VERSION 5.7 ;
  NOWIREEXTENSIONATPIN ON ;
  DIVIDERCHAR "/" ;
  BUSBITCHARS "[]" ;
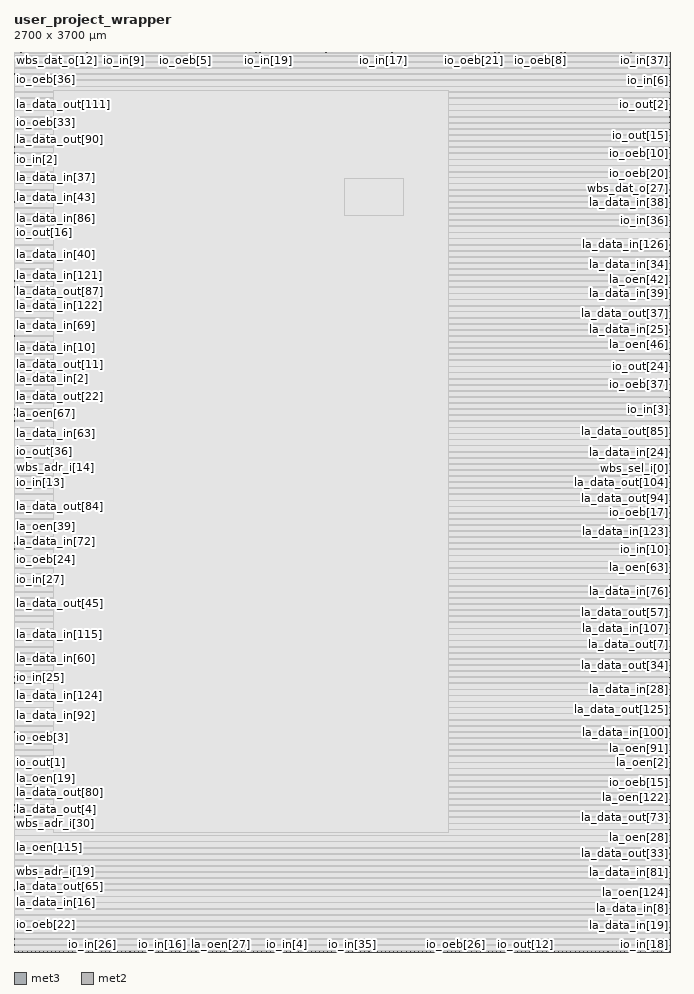
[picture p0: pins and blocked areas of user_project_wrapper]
MACRO user_project_wrapper
  CLASS BLOCK ;
  FOREIGN user_project_wrapper ;
  ORIGIN 0.000 0.000 ;
  SIZE 2700.000 BY 3700.000 ;
  PIN io_in[0]
    DIRECTION INPUT ;
    PORT
      LAYER met3 ;
        RECT 0.000 3659.800 4.000 3660.400 ;
    END
  END io_in[0]
  PIN io_in[10]
    DIRECTION INPUT ;
    PORT
      LAYER met3 ;
        RECT 2696.000 1655.160 2700.000 1655.760 ;
    END
  END io_in[10]
  PIN io_in[11]
    DIRECTION INPUT ;
    PORT
      LAYER met2 ;
        RECT 2061.810 3696.000 2062.090 3700.000 ;
    END
  END io_in[11]
  PIN io_in[12]
    DIRECTION INPUT ;
    PORT
      LAYER met2 ;
        RECT 2255.930 0.000 2256.210 4.000 ;
    END
  END io_in[12]
  PIN io_in[13]
    DIRECTION INPUT ;
    PORT
      LAYER met3 ;
        RECT 0.000 1931.240 4.000 1931.840 ;
    END
  END io_in[13]
  PIN io_in[14]
    DIRECTION INPUT ;
    PORT
      LAYER met3 ;
        RECT 0.000 730.360 4.000 730.960 ;
    END
  END io_in[14]
  PIN io_in[15]
    DIRECTION INPUT ;
    PORT
      LAYER met2 ;
        RECT 147.290 3696.000 147.570 3700.000 ;
    END
  END io_in[15]
  PIN io_in[16]
    DIRECTION INPUT ;
    PORT
      LAYER met2 ;
        RECT 611.890 0.000 612.170 4.000 ;
    END
  END io_in[16]
  PIN io_in[17]
    DIRECTION INPUT ;
    PORT
      LAYER met2 ;
        RECT 1519.930 3696.000 1520.210 3700.000 ;
    END
  END io_in[17]
  PIN io_in[18]
    DIRECTION INPUT ;
    PORT
      LAYER met2 ;
        RECT 2695.690 0.000 2695.970 4.000 ;
    END
  END io_in[18]
  PIN io_in[19]
    DIRECTION INPUT ;
    PORT
      LAYER met2 ;
        RECT 1045.210 3696.000 1045.490 3700.000 ;
    END
  END io_in[19]
  PIN io_in[1]
    DIRECTION INPUT ;
    PORT
      LAYER met3 ;
        RECT 2696.000 1153.320 2700.000 1153.920 ;
    END
  END io_in[1]
  PIN io_in[20]
    DIRECTION INPUT ;
    PORT
      LAYER met2 ;
        RECT 205.250 0.000 205.530 4.000 ;
    END
  END io_in[20]
  PIN io_in[21]
    DIRECTION INPUT ;
    PORT
      LAYER met3 ;
        RECT 0.000 1481.080 4.000 1481.680 ;
    END
  END io_in[21]
  PIN io_in[22]
    DIRECTION INPUT ;
    PORT
      LAYER met2 ;
        RECT 561.290 0.000 561.570 4.000 ;
    END
  END io_in[22]
  PIN io_in[23]
    DIRECTION INPUT ;
    PORT
      LAYER met2 ;
        RECT 2011.210 3696.000 2011.490 3700.000 ;
    END
  END io_in[23]
  PIN io_in[24]
    DIRECTION INPUT ;
    PORT
      LAYER met3 ;
        RECT 2696.000 352.280 2700.000 352.880 ;
    END
  END io_in[24]
  PIN io_in[25]
    DIRECTION INPUT ;
    PORT
      LAYER met3 ;
        RECT 0.000 1130.200 4.000 1130.800 ;
    END
  END io_in[25]
  PIN io_in[26]
    DIRECTION INPUT ;
    PORT
      LAYER met2 ;
        RECT 323.930 0.000 324.210 4.000 ;
    END
  END io_in[26]
  PIN io_in[27]
    DIRECTION INPUT ;
    PORT
      LAYER met3 ;
        RECT 0.000 1531.400 4.000 1532.000 ;
    END
  END io_in[27]
  PIN io_in[28]
    DIRECTION INPUT ;
    PORT
      LAYER met3 ;
        RECT 2696.000 2932.200 2700.000 2932.800 ;
    END
  END io_in[28]
  PIN io_in[29]
    DIRECTION INPUT ;
    PORT
      LAYER met2 ;
        RECT 663.410 0.000 663.690 4.000 ;
    END
  END io_in[29]
  PIN io_in[2]
    DIRECTION INPUT ;
    PORT
      LAYER met3 ;
        RECT 0.000 3258.600 4.000 3259.200 ;
    END
  END io_in[2]
  PIN io_in[30]
    DIRECTION INPUT ;
    PORT
      LAYER met2 ;
        RECT 2645.090 0.000 2645.370 4.000 ;
    END
  END io_in[30]
  PIN io_in[31]
    DIRECTION INPUT ;
    PORT
      LAYER met2 ;
        RECT 1028.650 3696.000 1028.930 3700.000 ;
    END
  END io_in[31]
  PIN io_in[32]
    DIRECTION INPUT ;
    PORT
      LAYER met3 ;
        RECT 0.000 454.280 4.000 454.880 ;
    END
  END io_in[32]
  PIN io_in[33]
    DIRECTION INPUT ;
    PORT
      LAYER met2 ;
        RECT 1163.890 3696.000 1164.170 3700.000 ;
    END
  END io_in[33]
  PIN io_in[34]
    DIRECTION INPUT ;
    PORT
      LAYER met2 ;
        RECT 960.570 3696.000 960.850 3700.000 ;
    END
  END io_in[34]
  PIN io_in[35]
    DIRECTION INPUT ;
    PORT
      LAYER met2 ;
        RECT 1391.130 0.000 1391.410 4.000 ;
    END
  END io_in[35]
  PIN io_in[36]
    DIRECTION INPUT ;
    PORT
      LAYER met3 ;
        RECT 2696.000 3007.000 2700.000 3007.600 ;
    END
  END io_in[36]
  PIN io_in[37]
    DIRECTION INPUT ;
    PORT
      LAYER met2 ;
        RECT 2621.170 3696.000 2621.450 3700.000 ;
    END
  END io_in[37]
  PIN io_in[3]
    DIRECTION INPUT ;
    PORT
      LAYER met3 ;
        RECT 2696.000 2230.440 2700.000 2231.040 ;
    END
  END io_in[3]
  PIN io_in[4]
    DIRECTION INPUT ;
    PORT
      LAYER met2 ;
        RECT 1120.650 0.000 1120.930 4.000 ;
    END
  END io_in[4]
  PIN io_in[5]
    DIRECTION INPUT ;
    PORT
      LAYER met2 ;
        RECT 442.610 0.000 442.890 4.000 ;
    END
  END io_in[5]
  PIN io_in[6]
    DIRECTION INPUT ;
    PORT
      LAYER met3 ;
        RECT 2696.000 3583.640 2700.000 3584.240 ;
    END
  END io_in[6]
  PIN io_in[7]
    DIRECTION INPUT ;
    PORT
      LAYER met2 ;
        RECT 1468.410 3696.000 1468.690 3700.000 ;
    END
  END io_in[7]
  PIN io_in[8]
    DIRECTION INPUT ;
    PORT
      LAYER met2 ;
        RECT 79.210 3696.000 79.490 3700.000 ;
    END
  END io_in[8]
  PIN io_in[9]
    DIRECTION INPUT ;
    PORT
      LAYER met2 ;
        RECT 452.730 3696.000 453.010 3700.000 ;
    END
  END io_in[9]
  PIN io_oeb[0]
    DIRECTION OUTPUT TRISTATE ;
    PORT
      LAYER met3 ;
        RECT 2696.000 2205.960 2700.000 2206.560 ;
    END
  END io_oeb[0]
  PIN io_oeb[10]
    DIRECTION OUTPUT TRISTATE ;
    PORT
      LAYER met3 ;
        RECT 2696.000 3283.080 2700.000 3283.680 ;
    END
  END io_oeb[10]
  PIN io_oeb[11]
    DIRECTION OUTPUT TRISTATE ;
    PORT
      LAYER met3 ;
        RECT 2696.000 1855.080 2700.000 1855.680 ;
    END
  END io_oeb[11]
  PIN io_oeb[12]
    DIRECTION OUTPUT TRISTATE ;
    PORT
      LAYER met3 ;
        RECT 0.000 1029.560 4.000 1030.160 ;
    END
  END io_oeb[12]
  PIN io_oeb[13]
    DIRECTION OUTPUT TRISTATE ;
    PORT
      LAYER met2 ;
        RECT 485.850 3696.000 486.130 3700.000 ;
    END
  END io_oeb[13]
  PIN io_oeb[14]
    DIRECTION OUTPUT TRISTATE ;
    PORT
      LAYER met2 ;
        RECT 544.730 0.000 545.010 4.000 ;
    END
  END io_oeb[14]
  PIN io_oeb[15]
    DIRECTION OUTPUT TRISTATE ;
    PORT
      LAYER met3 ;
        RECT 2696.000 727.640 2700.000 728.240 ;
    END
  END io_oeb[15]
  PIN io_oeb[16]
    DIRECTION OUTPUT TRISTATE ;
    PORT
      LAYER met3 ;
        RECT 0.000 855.480 4.000 856.080 ;
    END
  END io_oeb[16]
  PIN io_oeb[17]
    DIRECTION OUTPUT TRISTATE ;
    PORT
      LAYER met3 ;
        RECT 2696.000 1804.760 2700.000 1805.360 ;
    END
  END io_oeb[17]
  PIN io_oeb[18]
    DIRECTION OUTPUT TRISTATE ;
    PORT
      LAYER met2 ;
        RECT 2187.850 0.000 2188.130 4.000 ;
    END
  END io_oeb[18]
  PIN io_oeb[19]
    DIRECTION OUTPUT TRISTATE ;
    PORT
      LAYER met2 ;
        RECT 408.570 0.000 408.850 4.000 ;
    END
  END io_oeb[19]
  PIN io_oeb[1]
    DIRECTION OUTPUT TRISTATE ;
    PORT
      LAYER met2 ;
        RECT 604.530 3696.000 604.810 3700.000 ;
    END
  END io_oeb[1]
  PIN io_oeb[20]
    DIRECTION OUTPUT TRISTATE ;
    PORT
      LAYER met3 ;
        RECT 2696.000 3232.760 2700.000 3233.360 ;
    END
  END io_oeb[20]
  PIN io_oeb[21]
    DIRECTION OUTPUT TRISTATE ;
    PORT
      LAYER met2 ;
        RECT 1892.530 3696.000 1892.810 3700.000 ;
    END
  END io_oeb[21]
  PIN io_oeb[22]
    DIRECTION OUTPUT TRISTATE ;
    PORT
      LAYER met3 ;
        RECT 0.000 78.920 4.000 79.520 ;
    END
  END io_oeb[22]
  PIN io_oeb[23]
    DIRECTION OUTPUT TRISTATE ;
    PORT
      LAYER met3 ;
        RECT 0.000 403.960 4.000 404.560 ;
    END
  END io_oeb[23]
  PIN io_oeb[24]
    DIRECTION OUTPUT TRISTATE ;
    PORT
      LAYER met3 ;
        RECT 0.000 1581.720 4.000 1582.320 ;
    END
  END io_oeb[24]
  PIN io_oeb[25]
    DIRECTION OUTPUT TRISTATE ;
    PORT
      LAYER met2 ;
        RECT 2272.490 0.000 2272.770 4.000 ;
    END
  END io_oeb[25]
  PIN io_oeb[26]
    DIRECTION OUTPUT TRISTATE ;
    PORT
      LAYER met2 ;
        RECT 1815.250 0.000 1815.530 4.000 ;
    END
  END io_oeb[26]
  PIN io_oeb[27]
    DIRECTION OUTPUT TRISTATE ;
    PORT
      LAYER met3 ;
        RECT 2696.000 3632.600 2700.000 3633.200 ;
    END
  END io_oeb[27]
  PIN io_oeb[28]
    DIRECTION OUTPUT TRISTATE ;
    PORT
      LAYER met2 ;
        RECT 2434.410 3696.000 2434.690 3700.000 ;
    END
  END io_oeb[28]
  PIN io_oeb[29]
    DIRECTION OUTPUT TRISTATE ;
    PORT
      LAYER met3 ;
        RECT 2696.000 51.720 2700.000 52.320 ;
    END
  END io_oeb[29]
  PIN io_oeb[2]
    DIRECTION OUTPUT TRISTATE ;
    PORT
      LAYER met2 ;
        RECT 1401.250 3696.000 1401.530 3700.000 ;
    END
  END io_oeb[2]
  PIN io_oeb[30]
    DIRECTION OUTPUT TRISTATE ;
    PORT
      LAYER met3 ;
        RECT 0.000 1505.560 4.000 1506.160 ;
    END
  END io_oeb[30]
  PIN io_oeb[31]
    DIRECTION OUTPUT TRISTATE ;
    PORT
      LAYER met2 ;
        RECT 1645.970 0.000 1646.250 4.000 ;
    END
  END io_oeb[31]
  PIN io_oeb[32]
    DIRECTION OUTPUT TRISTATE ;
    PORT
      LAYER met2 ;
        RECT 62.650 3696.000 62.930 3700.000 ;
    END
  END io_oeb[32]
  PIN io_oeb[33]
    DIRECTION OUTPUT TRISTATE ;
    PORT
      LAYER met3 ;
        RECT 0.000 3409.560 4.000 3410.160 ;
    END
  END io_oeb[33]
  PIN io_oeb[34]
    DIRECTION OUTPUT TRISTATE ;
    PORT
      LAYER met2 ;
        RECT 460.090 0.000 460.370 4.000 ;
    END
  END io_oeb[34]
  PIN io_oeb[35]
    DIRECTION OUTPUT TRISTATE ;
    PORT
      LAYER met3 ;
        RECT 0.000 1706.840 4.000 1707.440 ;
    END
  END io_oeb[35]
  PIN io_oeb[36]
    DIRECTION OUTPUT TRISTATE ;
    PORT
      LAYER met3 ;
        RECT 0.000 3585.000 4.000 3585.600 ;
    END
  END io_oeb[36]
  PIN io_oeb[37]
    DIRECTION OUTPUT TRISTATE ;
    PORT
      LAYER met3 ;
        RECT 2696.000 2331.080 2700.000 2331.680 ;
    END
  END io_oeb[37]
  PIN io_oeb[3]
    DIRECTION OUTPUT TRISTATE ;
    PORT
      LAYER met3 ;
        RECT 0.000 879.960 4.000 880.560 ;
    END
  END io_oeb[3]
  PIN io_oeb[4]
    DIRECTION OUTPUT TRISTATE ;
    PORT
      LAYER met2 ;
        RECT 2569.650 3696.000 2569.930 3700.000 ;
    END
  END io_oeb[4]
  PIN io_oeb[5]
    DIRECTION OUTPUT TRISTATE ;
    PORT
      LAYER met2 ;
        RECT 706.650 3696.000 706.930 3700.000 ;
    END
  END io_oeb[5]
  PIN io_oeb[6]
    DIRECTION OUTPUT TRISTATE ;
    PORT
      LAYER met3 ;
        RECT 2696.000 3682.920 2700.000 3683.520 ;
    END
  END io_oeb[6]
  PIN io_oeb[7]
    DIRECTION OUTPUT TRISTATE ;
    PORT
      LAYER met2 ;
        RECT 1442.650 0.000 1442.930 4.000 ;
    END
  END io_oeb[7]
  PIN io_oeb[8]
    DIRECTION OUTPUT TRISTATE ;
    PORT
      LAYER met2 ;
        RECT 2163.010 3696.000 2163.290 3700.000 ;
    END
  END io_oeb[8]
  PIN io_oeb[9]
    DIRECTION OUTPUT TRISTATE ;
    PORT
      LAYER met2 ;
        RECT 595.330 0.000 595.610 4.000 ;
    END
  END io_oeb[9]
  PIN io_out[0]
    DIRECTION OUTPUT TRISTATE ;
    PORT
      LAYER met2 ;
        RECT 537.370 3696.000 537.650 3700.000 ;
    END
  END io_out[0]
  PIN io_out[10]
    DIRECTION OUTPUT TRISTATE ;
    PORT
      LAYER met2 ;
        RECT 401.210 3696.000 401.490 3700.000 ;
    END
  END io_out[10]
  PIN io_out[11]
    DIRECTION OUTPUT TRISTATE ;
    PORT
      LAYER met2 ;
        RECT 748.050 0.000 748.330 4.000 ;
    END
  END io_out[11]
  PIN io_out[12]
    DIRECTION OUTPUT TRISTATE ;
    PORT
      LAYER met2 ;
        RECT 2103.210 0.000 2103.490 4.000 ;
    END
  END io_out[12]
  PIN io_out[13]
    DIRECTION OUTPUT TRISTATE ;
    PORT
      LAYER met2 ;
        RECT 2204.410 0.000 2204.690 4.000 ;
    END
  END io_out[13]
  PIN io_out[14]
    DIRECTION OUTPUT TRISTATE ;
    PORT
      LAYER met3 ;
        RECT 2696.000 2131.160 2700.000 2131.760 ;
    END
  END io_out[14]
  PIN io_out[15]
    DIRECTION OUTPUT TRISTATE ;
    PORT
      LAYER met3 ;
        RECT 2696.000 3357.880 2700.000 3358.480 ;
    END
  END io_out[15]
  PIN io_out[16]
    DIRECTION OUTPUT TRISTATE ;
    PORT
      LAYER met3 ;
        RECT 0.000 2958.040 4.000 2958.640 ;
    END
  END io_out[16]
  PIN io_out[17]
    DIRECTION OUTPUT TRISTATE ;
    PORT
      LAYER met2 ;
        RECT 35.970 0.000 36.250 4.000 ;
    END
  END io_out[17]
  PIN io_out[18]
    DIRECTION OUTPUT TRISTATE ;
    PORT
      LAYER met2 ;
        RECT 290.810 0.000 291.090 4.000 ;
    END
  END io_out[18]
  PIN io_out[19]
    DIRECTION OUTPUT TRISTATE ;
    PORT
      LAYER met2 ;
        RECT 1587.090 3696.000 1587.370 3700.000 ;
    END
  END io_out[19]
  PIN io_out[1]
    DIRECTION OUTPUT TRISTATE ;
    PORT
      LAYER met3 ;
        RECT 0.000 779.320 4.000 779.920 ;
    END
  END io_out[1]
  PIN io_out[20]
    DIRECTION OUTPUT TRISTATE ;
    PORT
      LAYER met2 ;
        RECT 1696.570 0.000 1696.850 4.000 ;
    END
  END io_out[20]
  PIN io_out[21]
    DIRECTION OUTPUT TRISTATE ;
    PORT
      LAYER met2 ;
        RECT 341.410 0.000 341.690 4.000 ;
    END
  END io_out[21]
  PIN io_out[22]
    DIRECTION OUTPUT TRISTATE ;
    PORT
      LAYER met2 ;
        RECT 714.010 0.000 714.290 4.000 ;
    END
  END io_out[22]
  PIN io_out[23]
    DIRECTION OUTPUT TRISTATE ;
    PORT
      LAYER met2 ;
        RECT 2459.250 0.000 2459.530 4.000 ;
    END
  END io_out[23]
  PIN io_out[24]
    DIRECTION OUTPUT TRISTATE ;
    PORT
      LAYER met3 ;
        RECT 2696.000 2405.880 2700.000 2406.480 ;
    END
  END io_out[24]
  PIN io_out[25]
    DIRECTION OUTPUT TRISTATE ;
    PORT
      LAYER met3 ;
        RECT 0.000 2558.200 4.000 2558.800 ;
    END
  END io_out[25]
  PIN io_out[26]
    DIRECTION OUTPUT TRISTATE ;
    PORT
      LAYER met2 ;
        RECT 578.770 0.000 579.050 4.000 ;
    END
  END io_out[26]
  PIN io_out[27]
    DIRECTION OUTPUT TRISTATE ;
    PORT
      LAYER met2 ;
        RECT 553.930 3696.000 554.210 3700.000 ;
    END
  END io_out[27]
  PIN io_out[28]
    DIRECTION OUTPUT TRISTATE ;
    PORT
      LAYER met2 ;
        RECT 645.930 0.000 646.210 4.000 ;
    END
  END io_out[28]
  PIN io_out[29]
    DIRECTION OUTPUT TRISTATE ;
    PORT
      LAYER met3 ;
        RECT 0.000 1731.320 4.000 1731.920 ;
    END
  END io_out[29]
  PIN io_out[2]
    DIRECTION OUTPUT TRISTATE ;
    PORT
      LAYER met3 ;
        RECT 2696.000 3483.000 2700.000 3483.600 ;
    END
  END io_out[2]
  PIN io_out[30]
    DIRECTION OUTPUT TRISTATE ;
    PORT
      LAYER met2 ;
        RECT 1129.850 3696.000 1130.130 3700.000 ;
    END
  END io_out[30]
  PIN io_out[31]
    DIRECTION OUTPUT TRISTATE ;
    PORT
      LAYER met3 ;
        RECT 2696.000 979.240 2700.000 979.840 ;
    END
  END io_out[31]
  PIN io_out[32]
    DIRECTION OUTPUT TRISTATE ;
    PORT
      LAYER met2 ;
        RECT 1655.170 3696.000 1655.450 3700.000 ;
    END
  END io_out[32]
  PIN io_out[33]
    DIRECTION OUTPUT TRISTATE ;
    PORT
      LAYER met2 ;
        RECT 1011.170 3696.000 1011.450 3700.000 ;
    END
  END io_out[33]
  PIN io_out[34]
    DIRECTION OUTPUT TRISTATE ;
    PORT
      LAYER met2 ;
        RECT 316.570 3696.000 316.850 3700.000 ;
    END
  END io_out[34]
  PIN io_out[35]
    DIRECTION OUTPUT TRISTATE ;
    PORT
      LAYER met3 ;
        RECT 2696.000 1128.840 2700.000 1129.440 ;
    END
  END io_out[35]
  PIN io_out[36]
    DIRECTION OUTPUT TRISTATE ;
    PORT
      LAYER met3 ;
        RECT 0.000 2056.360 4.000 2056.960 ;
    END
  END io_out[36]
  PIN io_out[37]
    DIRECTION OUTPUT TRISTATE ;
    PORT
      LAYER met3 ;
        RECT 2696.000 3432.680 2700.000 3433.280 ;
    END
  END io_out[37]
  PIN io_out[3]
    DIRECTION OUTPUT TRISTATE ;
    PORT
      LAYER met2 ;
        RECT 1705.770 3696.000 1706.050 3700.000 ;
    END
  END io_out[3]
  PIN io_out[4]
    DIRECTION OUTPUT TRISTATE ;
    PORT
      LAYER met3 ;
        RECT 2696.000 1530.040 2700.000 1530.640 ;
    END
  END io_out[4]
  PIN io_out[5]
    DIRECTION OUTPUT TRISTATE ;
    PORT
      LAYER met3 ;
        RECT 0.000 1906.760 4.000 1907.360 ;
    END
  END io_out[5]
  PIN io_out[6]
    DIRECTION OUTPUT TRISTATE ;
    PORT
      LAYER met2 ;
        RECT 2231.090 3696.000 2231.370 3700.000 ;
    END
  END io_out[6]
  PIN io_out[7]
    DIRECTION OUTPUT TRISTATE ;
    PORT
      LAYER met2 ;
        RECT 764.610 0.000 764.890 4.000 ;
    END
  END io_out[7]
  PIN io_out[8]
    DIRECTION OUTPUT TRISTATE ;
    PORT
      LAYER met2 ;
        RECT 1680.010 0.000 1680.290 4.000 ;
    END
  END io_out[8]
  PIN io_out[9]
    DIRECTION OUTPUT TRISTATE ;
    PORT
      LAYER met2 ;
        RECT 164.770 3696.000 165.050 3700.000 ;
    END
  END io_out[9]
  PIN la_data_in[0]
    DIRECTION INPUT ;
    PORT
      LAYER met2 ;
        RECT 1459.210 0.000 1459.490 4.000 ;
    END
  END la_data_in[0]
  PIN la_data_in[100]
    DIRECTION INPUT ;
    PORT
      LAYER met3 ;
        RECT 2696.000 903.080 2700.000 903.680 ;
    END
  END la_data_in[100]
  PIN la_data_in[101]
    DIRECTION INPUT ;
    PORT
      LAYER met3 ;
        RECT 2696.000 427.080 2700.000 427.680 ;
    END
  END la_data_in[101]
  PIN la_data_in[102]
    DIRECTION INPUT ;
    PORT
      LAYER met2 ;
        RECT 723.210 3696.000 723.490 3700.000 ;
    END
  END la_data_in[102]
  PIN la_data_in[103]
    DIRECTION INPUT ;
    PORT
      LAYER met2 ;
        RECT 2383.810 3696.000 2384.090 3700.000 ;
    END
  END la_data_in[103]
  PIN la_data_in[104]
    DIRECTION INPUT ;
    PORT
      LAYER met2 ;
        RECT 1757.290 3696.000 1757.570 3700.000 ;
    END
  END la_data_in[104]
  PIN la_data_in[105]
    DIRECTION INPUT ;
    PORT
      LAYER met2 ;
        RECT 2357.130 0.000 2357.410 4.000 ;
    END
  END la_data_in[105]
  PIN la_data_in[106]
    DIRECTION INPUT ;
    PORT
      LAYER met3 ;
        RECT 0.000 1456.600 4.000 1457.200 ;
    END
  END la_data_in[106]
  PIN la_data_in[107]
    DIRECTION INPUT ;
    PORT
      LAYER met3 ;
        RECT 2696.000 1328.760 2700.000 1329.360 ;
    END
  END la_data_in[107]
  PIN la_data_in[108]
    DIRECTION INPUT ;
    PORT
      LAYER met2 ;
        RECT 2553.090 3696.000 2553.370 3700.000 ;
    END
  END la_data_in[108]
  PIN la_data_in[109]
    DIRECTION INPUT ;
    PORT
      LAYER met3 ;
        RECT 0.000 1255.320 4.000 1255.920 ;
    END
  END la_data_in[109]
  PIN la_data_in[10]
    DIRECTION INPUT ;
    PORT
      LAYER met3 ;
        RECT 0.000 2483.400 4.000 2484.000 ;
    END
  END la_data_in[10]
  PIN la_data_in[110]
    DIRECTION INPUT ;
    PORT
      LAYER met2 ;
        RECT 53.450 0.000 53.730 4.000 ;
    END
  END la_data_in[110]
  PIN la_data_in[111]
    DIRECTION INPUT ;
    PORT
      LAYER met3 ;
        RECT 0.000 1230.840 4.000 1231.440 ;
    END
  END la_data_in[111]
  PIN la_data_in[112]
    DIRECTION INPUT ;
    PORT
      LAYER met2 ;
        RECT 2509.850 0.000 2510.130 4.000 ;
    END
  END la_data_in[112]
  PIN la_data_in[113]
    DIRECTION INPUT ;
    PORT
      LAYER met2 ;
        RECT 2679.130 0.000 2679.410 4.000 ;
    END
  END la_data_in[113]
  PIN la_data_in[114]
    DIRECTION INPUT ;
    PORT
      LAYER met2 ;
        RECT 757.250 3696.000 757.530 3700.000 ;
    END
  END la_data_in[114]
  PIN la_data_in[115]
    DIRECTION INPUT ;
    PORT
      LAYER met3 ;
        RECT 0.000 1305.640 4.000 1306.240 ;
    END
  END la_data_in[115]
  PIN la_data_in[116]
    DIRECTION INPUT ;
    PORT
      LAYER met2 ;
        RECT 476.650 0.000 476.930 4.000 ;
    END
  END la_data_in[116]
  PIN la_data_in[117]
    DIRECTION INPUT ;
    PORT
      LAYER met2 ;
        RECT 1977.170 3696.000 1977.450 3700.000 ;
    END
  END la_data_in[117]
  PIN la_data_in[118]
    DIRECTION INPUT ;
    PORT
      LAYER met2 ;
        RECT 1933.930 0.000 1934.210 4.000 ;
    END
  END la_data_in[118]
  PIN la_data_in[119]
    DIRECTION INPUT ;
    PORT
      LAYER met2 ;
        RECT 188.690 0.000 188.970 4.000 ;
    END
  END la_data_in[119]
  PIN la_data_in[11]
    DIRECTION INPUT ;
    PORT
      LAYER met3 ;
        RECT 0.000 3434.040 4.000 3434.640 ;
    END
  END la_data_in[11]
  PIN la_data_in[120]
    DIRECTION INPUT ;
    PORT
      LAYER met3 ;
        RECT 0.000 980.600 4.000 981.200 ;
    END
  END la_data_in[120]
  PIN la_data_in[121]
    DIRECTION INPUT ;
    PORT
      LAYER met3 ;
        RECT 0.000 2782.600 4.000 2783.200 ;
    END
  END la_data_in[121]
  PIN la_data_in[122]
    DIRECTION INPUT ;
    PORT
      LAYER met3 ;
        RECT 0.000 2657.480 4.000 2658.080 ;
    END
  END la_data_in[122]
  PIN la_data_in[123]
    DIRECTION INPUT ;
    PORT
      LAYER met3 ;
        RECT 2696.000 1729.960 2700.000 1730.560 ;
    END
  END la_data_in[123]
  PIN la_data_in[124]
    DIRECTION INPUT ;
    PORT
      LAYER met3 ;
        RECT 0.000 1055.400 4.000 1056.000 ;
    END
  END la_data_in[124]
  PIN la_data_in[125]
    DIRECTION INPUT ;
    PORT
      LAYER met3 ;
        RECT 2696.000 301.960 2700.000 302.560 ;
    END
  END la_data_in[125]
  PIN la_data_in[126]
    DIRECTION INPUT ;
    PORT
      LAYER met3 ;
        RECT 2696.000 2906.360 2700.000 2906.960 ;
    END
  END la_data_in[126]
  PIN la_data_in[127]
    DIRECTION INPUT ;
    PORT
      LAYER met3 ;
        RECT 0.000 3559.160 4.000 3559.760 ;
    END
  END la_data_in[127]
  PIN la_data_in[12]
    DIRECTION INPUT ;
    PORT
      LAYER met3 ;
        RECT 2696.000 3658.440 2700.000 3659.040 ;
    END
  END la_data_in[12]
  PIN la_data_in[13]
    DIRECTION INPUT ;
    PORT
      LAYER met2 ;
        RECT 782.090 0.000 782.370 4.000 ;
    END
  END la_data_in[13]
  PIN la_data_in[14]
    DIRECTION INPUT ;
    PORT
      LAYER met2 ;
        RECT 730.570 0.000 730.850 4.000 ;
    END
  END la_data_in[14]
  PIN la_data_in[15]
    DIRECTION INPUT ;
    PORT
      LAYER met2 ;
        RECT 944.010 3696.000 944.290 3700.000 ;
    END
  END la_data_in[15]
  PIN la_data_in[16]
    DIRECTION INPUT ;
    PORT
      LAYER met3 ;
        RECT 0.000 204.040 4.000 204.640 ;
    END
  END la_data_in[16]
  PIN la_data_in[17]
    DIRECTION INPUT ;
    PORT
      LAYER met2 ;
        RECT 222.730 0.000 223.010 4.000 ;
    END
  END la_data_in[17]
  PIN la_data_in[18]
    DIRECTION INPUT ;
    PORT
      LAYER met2 ;
        RECT 503.330 3696.000 503.610 3700.000 ;
    END
  END la_data_in[18]
  PIN la_data_in[19]
    DIRECTION INPUT ;
    PORT
      LAYER met3 ;
        RECT 2696.000 77.560 2700.000 78.160 ;
    END
  END la_data_in[19]
  PIN la_data_in[1]
    DIRECTION INPUT ;
    PORT
      LAYER met2 ;
        RECT 2214.530 3696.000 2214.810 3700.000 ;
    END
  END la_data_in[1]
  PIN la_data_in[20]
    DIRECTION INPUT ;
    PORT
      LAYER met3 ;
        RECT 2696.000 1104.360 2700.000 1104.960 ;
    END
  END la_data_in[20]
  PIN la_data_in[21]
    DIRECTION INPUT ;
    PORT
      LAYER met2 ;
        RECT 1967.970 0.000 1968.250 4.000 ;
    END
  END la_data_in[21]
  PIN la_data_in[22]
    DIRECTION INPUT ;
    PORT
      LAYER met2 ;
        RECT 256.770 0.000 257.050 4.000 ;
    END
  END la_data_in[22]
  PIN la_data_in[23]
    DIRECTION INPUT ;
    PORT
      LAYER met3 ;
        RECT 2696.000 3382.360 2700.000 3382.960 ;
    END
  END la_data_in[23]
  PIN la_data_in[24]
    DIRECTION INPUT ;
    PORT
      LAYER met3 ;
        RECT 2696.000 2055.000 2700.000 2055.600 ;
    END
  END la_data_in[24]
  PIN la_data_in[25]
    DIRECTION INPUT ;
    PORT
      LAYER met3 ;
        RECT 2696.000 2556.840 2700.000 2557.440 ;
    END
  END la_data_in[25]
  PIN la_data_in[26]
    DIRECTION INPUT ;
    PORT
      LAYER met2 ;
        RECT 791.290 3696.000 791.570 3700.000 ;
    END
  END la_data_in[26]
  PIN la_data_in[27]
    DIRECTION INPUT ;
    PORT
      LAYER met3 ;
        RECT 0.000 2106.680 4.000 2107.280 ;
    END
  END la_data_in[27]
  PIN la_data_in[28]
    DIRECTION INPUT ;
    PORT
      LAYER met3 ;
        RECT 2696.000 1078.520 2700.000 1079.120 ;
    END
  END la_data_in[28]
  PIN la_data_in[29]
    DIRECTION INPUT ;
    PORT
      LAYER met2 ;
        RECT 672.610 3696.000 672.890 3700.000 ;
    END
  END la_data_in[29]
  PIN la_data_in[2]
    DIRECTION INPUT ;
    PORT
      LAYER met3 ;
        RECT 0.000 2356.920 4.000 2357.520 ;
    END
  END la_data_in[2]
  PIN la_data_in[30]
    DIRECTION INPUT ;
    PORT
      LAYER met2 ;
        RECT 917.330 0.000 917.610 4.000 ;
    END
  END la_data_in[30]
  PIN la_data_in[31]
    DIRECTION INPUT ;
    PORT
      LAYER met3 ;
        RECT 2696.000 3458.520 2700.000 3459.120 ;
    END
  END la_data_in[31]
  PIN la_data_in[32]
    DIRECTION INPUT ;
    PORT
      LAYER met3 ;
        RECT 2696.000 1754.440 2700.000 1755.040 ;
    END
  END la_data_in[32]
  PIN la_data_in[33]
    DIRECTION INPUT ;
    PORT
      LAYER met3 ;
        RECT 0.000 504.600 4.000 505.200 ;
    END
  END la_data_in[33]
  PIN la_data_in[34]
    DIRECTION INPUT ;
    PORT
      LAYER met3 ;
        RECT 2696.000 2857.400 2700.000 2858.000 ;
    END
  END la_data_in[34]
  PIN la_data_in[35]
    DIRECTION INPUT ;
    PORT
      LAYER met2 ;
        RECT 1841.930 3696.000 1842.210 3700.000 ;
    END
  END la_data_in[35]
  PIN la_data_in[36]
    DIRECTION INPUT ;
    PORT
      LAYER met3 ;
        RECT 0.000 2758.120 4.000 2758.720 ;
    END
  END la_data_in[36]
  PIN la_data_in[37]
    DIRECTION INPUT ;
    PORT
      LAYER met3 ;
        RECT 0.000 3183.800 4.000 3184.400 ;
    END
  END la_data_in[37]
  PIN la_data_in[38]
    DIRECTION INPUT ;
    PORT
      LAYER met3 ;
        RECT 2696.000 3081.800 2700.000 3082.400 ;
    END
  END la_data_in[38]
  PIN la_data_in[39]
    DIRECTION INPUT ;
    PORT
      LAYER met3 ;
        RECT 2696.000 2706.440 2700.000 2707.040 ;
    END
  END la_data_in[39]
  PIN la_data_in[3]
    DIRECTION INPUT ;
    PORT
      LAYER met2 ;
        RECT 239.290 0.000 239.570 4.000 ;
    END
  END la_data_in[3]
  PIN la_data_in[40]
    DIRECTION INPUT ;
    PORT
      LAYER met3 ;
        RECT 0.000 2832.920 4.000 2833.520 ;
    END
  END la_data_in[40]
  PIN la_data_in[41]
    DIRECTION INPUT ;
    PORT
      LAYER met2 ;
        RECT 1604.570 3696.000 1604.850 3700.000 ;
    END
  END la_data_in[41]
  PIN la_data_in[42]
    DIRECTION INPUT ;
    PORT
      LAYER met3 ;
        RECT 0.000 28.600 4.000 29.200 ;
    END
  END la_data_in[42]
  PIN la_data_in[43]
    DIRECTION INPUT ;
    PORT
      LAYER met3 ;
        RECT 0.000 3133.480 4.000 3134.080 ;
    END
  END la_data_in[43]
  PIN la_data_in[44]
    DIRECTION INPUT ;
    PORT
      LAYER met3 ;
        RECT 2696.000 1003.720 2700.000 1004.320 ;
    END
  END la_data_in[44]
  PIN la_data_in[45]
    DIRECTION INPUT ;
    PORT
      LAYER met2 ;
        RECT 1638.610 3696.000 1638.890 3700.000 ;
    END
  END la_data_in[45]
  PIN la_data_in[46]
    DIRECTION INPUT ;
    PORT
      LAYER met3 ;
        RECT 0.000 3383.720 4.000 3384.320 ;
    END
  END la_data_in[46]
  PIN la_data_in[47]
    DIRECTION INPUT ;
    PORT
      LAYER met2 ;
        RECT 933.890 0.000 934.170 4.000 ;
    END
  END la_data_in[47]
  PIN la_data_in[48]
    DIRECTION INPUT ;
    PORT
      LAYER met2 ;
        RECT 2391.170 0.000 2391.450 4.000 ;
    END
  END la_data_in[48]
  PIN la_data_in[49]
    DIRECTION INPUT ;
    PORT
      LAYER met2 ;
        RECT 1875.050 3696.000 1875.330 3700.000 ;
    END
  END la_data_in[49]
  PIN la_data_in[4]
    DIRECTION INPUT ;
    PORT
      LAYER met2 ;
        RECT 2.850 0.000 3.130 4.000 ;
    END
  END la_data_in[4]
  PIN la_data_in[50]
    DIRECTION INPUT ;
    PORT
      LAYER met3 ;
        RECT 2696.000 2781.240 2700.000 2781.840 ;
    END
  END la_data_in[50]
  PIN la_data_in[51]
    DIRECTION INPUT ;
    PORT
      LAYER met3 ;
        RECT 0.000 1330.120 4.000 1330.720 ;
    END
  END la_data_in[51]
  PIN la_data_in[52]
    DIRECTION INPUT ;
    PORT
      LAYER met2 ;
        RECT 172.130 0.000 172.410 4.000 ;
    END
  END la_data_in[52]
  PIN la_data_in[53]
    DIRECTION INPUT ;
    PORT
      LAYER met3 ;
        RECT 2696.000 2006.040 2700.000 2006.640 ;
    END
  END la_data_in[53]
  PIN la_data_in[54]
    DIRECTION INPUT ;
    PORT
      LAYER met2 ;
        RECT 1959.690 3696.000 1959.970 3700.000 ;
    END
  END la_data_in[54]
  PIN la_data_in[55]
    DIRECTION INPUT ;
    PORT
      LAYER met2 ;
        RECT 2587.130 3696.000 2587.410 3700.000 ;
    END
  END la_data_in[55]
  PIN la_data_in[56]
    DIRECTION INPUT ;
    PORT
      LAYER met3 ;
        RECT 2696.000 3307.560 2700.000 3308.160 ;
    END
  END la_data_in[56]
  PIN la_data_in[57]
    DIRECTION INPUT ;
    PORT
      LAYER met3 ;
        RECT 2696.000 3408.200 2700.000 3408.800 ;
    END
  END la_data_in[57]
  PIN la_data_in[58]
    DIRECTION INPUT ;
    PORT
      LAYER met2 ;
        RECT 2577.010 0.000 2577.290 4.000 ;
    END
  END la_data_in[58]
  PIN la_data_in[59]
    DIRECTION INPUT ;
    PORT
      LAYER met3 ;
        RECT 2696.000 227.160 2700.000 227.760 ;
    END
  END la_data_in[59]
  PIN la_data_in[5]
    DIRECTION INPUT ;
    PORT
      LAYER met2 ;
        RECT 2153.810 0.000 2154.090 4.000 ;
    END
  END la_data_in[5]
  PIN la_data_in[60]
    DIRECTION INPUT ;
    PORT
      LAYER met3 ;
        RECT 0.000 1205.000 4.000 1205.600 ;
    END
  END la_data_in[60]
  PIN la_data_in[61]
    DIRECTION INPUT ;
    PORT
      LAYER met2 ;
        RECT 2027.770 3696.000 2028.050 3700.000 ;
    END
  END la_data_in[61]
  PIN la_data_in[62]
    DIRECTION INPUT ;
    PORT
      LAYER met3 ;
        RECT 2696.000 527.720 2700.000 528.320 ;
    END
  END la_data_in[62]
  PIN la_data_in[63]
    DIRECTION INPUT ;
    PORT
      LAYER met3 ;
        RECT 0.000 2132.520 4.000 2133.120 ;
    END
  END la_data_in[63]
  PIN la_data_in[64]
    DIRECTION INPUT ;
    PORT
      LAYER met2 ;
        RECT 1943.130 3696.000 1943.410 3700.000 ;
    END
  END la_data_in[64]
  PIN la_data_in[65]
    DIRECTION INPUT ;
    PORT
      LAYER met3 ;
        RECT 0.000 579.400 4.000 580.000 ;
    END
  END la_data_in[65]
  PIN la_data_in[66]
    DIRECTION INPUT ;
    PORT
      LAYER met2 ;
        RECT 1916.450 0.000 1916.730 4.000 ;
    END
  END la_data_in[66]
  PIN la_data_in[67]
    DIRECTION INPUT ;
    PORT
      LAYER met3 ;
        RECT 2696.000 1679.640 2700.000 1680.240 ;
    END
  END la_data_in[67]
  PIN la_data_in[68]
    DIRECTION INPUT ;
    PORT
      LAYER met3 ;
        RECT 0.000 3209.640 4.000 3210.240 ;
    END
  END la_data_in[68]
  PIN la_data_in[69]
    DIRECTION INPUT ;
    PORT
      LAYER met3 ;
        RECT 0.000 2608.520 4.000 2609.120 ;
    END
  END la_data_in[69]
  PIN la_data_in[6]
    DIRECTION INPUT ;
    PORT
      LAYER met3 ;
        RECT 2696.000 3533.320 2700.000 3533.920 ;
    END
  END la_data_in[6]
  PIN la_data_in[70]
    DIRECTION INPUT ;
    PORT
      LAYER met2 ;
        RECT 1621.130 3696.000 1621.410 3700.000 ;
    END
  END la_data_in[70]
  PIN la_data_in[71]
    DIRECTION INPUT ;
    PORT
      LAYER met2 ;
        RECT 2407.730 0.000 2408.010 4.000 ;
    END
  END la_data_in[71]
  PIN la_data_in[72]
    DIRECTION INPUT ;
    PORT
      LAYER met3 ;
        RECT 0.000 1656.520 4.000 1657.120 ;
    END
  END la_data_in[72]
  PIN la_data_in[73]
    DIRECTION INPUT ;
    PORT
      LAYER met2 ;
        RECT 12.050 3696.000 12.330 3700.000 ;
    END
  END la_data_in[73]
  PIN la_data_in[74]
    DIRECTION INPUT ;
    PORT
      LAYER met2 ;
        RECT 368.090 3696.000 368.370 3700.000 ;
    END
  END la_data_in[74]
  PIN la_data_in[75]
    DIRECTION INPUT ;
    PORT
      LAYER met2 ;
        RECT 1154.690 0.000 1154.970 4.000 ;
    END
  END la_data_in[75]
  PIN la_data_in[76]
    DIRECTION INPUT ;
    PORT
      LAYER met3 ;
        RECT 2696.000 1479.720 2700.000 1480.320 ;
    END
  END la_data_in[76]
  PIN la_data_in[77]
    DIRECTION INPUT ;
    PORT
      LAYER met3 ;
        RECT 2696.000 703.160 2700.000 703.760 ;
    END
  END la_data_in[77]
  PIN la_data_in[78]
    DIRECTION INPUT ;
    PORT
      LAYER met3 ;
        RECT 0.000 1180.520 4.000 1181.120 ;
    END
  END la_data_in[78]
  PIN la_data_in[79]
    DIRECTION INPUT ;
    PORT
      LAYER met2 ;
        RECT 2662.570 0.000 2662.850 4.000 ;
    END
  END la_data_in[79]
  PIN la_data_in[7]
    DIRECTION INPUT ;
    PORT
      LAYER met3 ;
        RECT 2696.000 2306.600 2700.000 2307.200 ;
    END
  END la_data_in[7]
  PIN la_data_in[80]
    DIRECTION INPUT ;
    PORT
      LAYER met2 ;
        RECT 2374.610 0.000 2374.890 4.000 ;
    END
  END la_data_in[80]
  PIN la_data_in[81]
    DIRECTION INPUT ;
    PORT
      LAYER met3 ;
        RECT 2696.000 327.800 2700.000 328.400 ;
    END
  END la_data_in[81]
  PIN la_data_in[82]
    DIRECTION INPUT ;
    PORT
      LAYER met3 ;
        RECT 2696.000 3332.040 2700.000 3332.640 ;
    END
  END la_data_in[82]
  PIN la_data_in[83]
    DIRECTION INPUT ;
    PORT
      LAYER met2 ;
        RECT 1147.330 3696.000 1147.610 3700.000 ;
    END
  END la_data_in[83]
  PIN la_data_in[84]
    DIRECTION INPUT ;
    PORT
      LAYER met2 ;
        RECT 138.090 0.000 138.370 4.000 ;
    END
  END la_data_in[84]
  PIN la_data_in[85]
    DIRECTION INPUT ;
    PORT
      LAYER met2 ;
        RECT 1730.610 0.000 1730.890 4.000 ;
    END
  END la_data_in[85]
  PIN la_data_in[86]
    DIRECTION INPUT ;
    PORT
      LAYER met3 ;
        RECT 0.000 2983.880 4.000 2984.480 ;
    END
  END la_data_in[86]
  PIN la_data_in[87]
    DIRECTION INPUT ;
    PORT
      LAYER met3 ;
        RECT 0.000 1105.720 4.000 1106.320 ;
    END
  END la_data_in[87]
  PIN la_data_in[88]
    DIRECTION INPUT ;
    PORT
      LAYER met2 ;
        RECT 2340.570 0.000 2340.850 4.000 ;
    END
  END la_data_in[88]
  PIN la_data_in[89]
    DIRECTION INPUT ;
    PORT
      LAYER met2 ;
        RECT 519.890 3696.000 520.170 3700.000 ;
    END
  END la_data_in[89]
  PIN la_data_in[8]
    DIRECTION INPUT ;
    PORT
      LAYER met3 ;
        RECT 2696.000 176.840 2700.000 177.440 ;
    END
  END la_data_in[8]
  PIN la_data_in[90]
    DIRECTION INPUT ;
    PORT
      LAYER met2 ;
        RECT 892.490 3696.000 892.770 3700.000 ;
    END
  END la_data_in[90]
  PIN la_data_in[91]
    DIRECTION INPUT ;
    PORT
      LAYER met2 ;
        RECT 2299.170 3696.000 2299.450 3700.000 ;
    END
  END la_data_in[91]
  PIN la_data_in[92]
    DIRECTION INPUT ;
    PORT
      LAYER met3 ;
        RECT 0.000 1005.080 4.000 1005.680 ;
    END
  END la_data_in[92]
  PIN la_data_in[93]
    DIRECTION INPUT ;
    PORT
      LAYER met3 ;
        RECT 0.000 1882.280 4.000 1882.880 ;
    END
  END la_data_in[93]
  PIN la_data_in[94]
    DIRECTION INPUT ;
    PORT
      LAYER met2 ;
        RECT 1188.730 0.000 1189.010 4.000 ;
    END
  END la_data_in[94]
  PIN la_data_in[95]
    DIRECTION INPUT ;
    PORT
      LAYER met2 ;
        RECT 350.610 3696.000 350.890 3700.000 ;
    END
  END la_data_in[95]
  PIN la_data_in[96]
    DIRECTION INPUT ;
    PORT
      LAYER met3 ;
        RECT 2696.000 1054.040 2700.000 1054.640 ;
    END
  END la_data_in[96]
  PIN la_data_in[97]
    DIRECTION INPUT ;
    PORT
      LAYER met3 ;
        RECT 0.000 2733.640 4.000 2734.240 ;
    END
  END la_data_in[97]
  PIN la_data_in[98]
    DIRECTION INPUT ;
    PORT
      LAYER met2 ;
        RECT 2069.170 0.000 2069.450 4.000 ;
    END
  END la_data_in[98]
  PIN la_data_in[99]
    DIRECTION INPUT ;
    PORT
      LAYER met3 ;
        RECT 2696.000 2381.400 2700.000 2382.000 ;
    END
  END la_data_in[99]
  PIN la_data_in[9]
    DIRECTION INPUT ;
    PORT
      LAYER met3 ;
        RECT 0.000 2007.400 4.000 2008.000 ;
    END
  END la_data_in[9]
  PIN la_data_out[0]
    DIRECTION OUTPUT TRISTATE ;
    PORT
      LAYER met2 ;
        RECT 1425.170 0.000 1425.450 4.000 ;
    END
  END la_data_out[0]
  PIN la_data_out[100]
    DIRECTION OUTPUT TRISTATE ;
    PORT
      LAYER met3 ;
        RECT 2696.000 27.240 2700.000 27.840 ;
    END
  END la_data_out[100]
  PIN la_data_out[101]
    DIRECTION OUTPUT TRISTATE ;
    PORT
      LAYER met3 ;
        RECT 2696.000 477.400 2700.000 478.000 ;
    END
  END la_data_out[101]
  PIN la_data_out[102]
    DIRECTION OUTPUT TRISTATE ;
    PORT
      LAYER met2 ;
        RECT 375.450 0.000 375.730 4.000 ;
    END
  END la_data_out[102]
  PIN la_data_out[103]
    DIRECTION OUTPUT TRISTATE ;
    PORT
      LAYER met2 ;
        RECT 154.650 0.000 154.930 4.000 ;
    END
  END la_data_out[103]
  PIN la_data_out[104]
    DIRECTION OUTPUT TRISTATE ;
    PORT
      LAYER met3 ;
        RECT 2696.000 1929.880 2700.000 1930.480 ;
    END
  END la_data_out[104]
  PIN la_data_out[105]
    DIRECTION OUTPUT TRISTATE ;
    PORT
      LAYER met3 ;
        RECT 0.000 704.520 4.000 705.120 ;
    END
  END la_data_out[105]
  PIN la_data_out[106]
    DIRECTION OUTPUT TRISTATE ;
    PORT
      LAYER met2 ;
        RECT 951.370 0.000 951.650 4.000 ;
    END
  END la_data_out[106]
  PIN la_data_out[107]
    DIRECTION OUTPUT TRISTATE ;
    PORT
      LAYER met3 ;
        RECT 0.000 3008.360 4.000 3008.960 ;
    END
  END la_data_out[107]
  PIN la_data_out[108]
    DIRECTION OUTPUT TRISTATE ;
    PORT
      LAYER met3 ;
        RECT 0.000 2909.080 4.000 2909.680 ;
    END
  END la_data_out[108]
  PIN la_data_out[109]
    DIRECTION OUTPUT TRISTATE ;
    PORT
      LAYER met3 ;
        RECT 0.000 2808.440 4.000 2809.040 ;
    END
  END la_data_out[109]
  PIN la_data_out[10]
    DIRECTION OUTPUT TRISTATE ;
    PORT
      LAYER met2 ;
        RECT 2502.490 3696.000 2502.770 3700.000 ;
    END
  END la_data_out[10]
  PIN la_data_out[110]
    DIRECTION OUTPUT TRISTATE ;
    PORT
      LAYER met2 ;
        RECT 1543.850 0.000 1544.130 4.000 ;
    END
  END la_data_out[110]
  PIN la_data_out[111]
    DIRECTION OUTPUT TRISTATE ;
    PORT
      LAYER met3 ;
        RECT 0.000 3484.360 4.000 3484.960 ;
    END
  END la_data_out[111]
  PIN la_data_out[112]
    DIRECTION OUTPUT TRISTATE ;
    PORT
      LAYER met2 ;
        RECT 1797.770 0.000 1798.050 4.000 ;
    END
  END la_data_out[112]
  PIN la_data_out[113]
    DIRECTION OUTPUT TRISTATE ;
    PORT
      LAYER met3 ;
        RECT 0.000 2157.000 4.000 2157.600 ;
    END
  END la_data_out[113]
  PIN la_data_out[114]
    DIRECTION OUTPUT TRISTATE ;
    PORT
      LAYER met2 ;
        RECT 2366.330 3696.000 2366.610 3700.000 ;
    END
  END la_data_out[114]
  PIN la_data_out[115]
    DIRECTION OUTPUT TRISTATE ;
    PORT
      LAYER met3 ;
        RECT 2696.000 3507.480 2700.000 3508.080 ;
    END
  END la_data_out[115]
  PIN la_data_out[116]
    DIRECTION OUTPUT TRISTATE ;
    PORT
      LAYER met2 ;
        RECT 2052.610 0.000 2052.890 4.000 ;
    END
  END la_data_out[116]
  PIN la_data_out[117]
    DIRECTION OUTPUT TRISTATE ;
    PORT
      LAYER met3 ;
        RECT 2696.000 1504.200 2700.000 1504.800 ;
    END
  END la_data_out[117]
  PIN la_data_out[118]
    DIRECTION OUTPUT TRISTATE ;
    PORT
      LAYER met3 ;
        RECT 2696.000 1905.400 2700.000 1906.000 ;
    END
  END la_data_out[118]
  PIN la_data_out[119]
    DIRECTION OUTPUT TRISTATE ;
    PORT
      LAYER met3 ;
        RECT 0.000 478.760 4.000 479.360 ;
    END
  END la_data_out[119]
  PIN la_data_out[11]
    DIRECTION OUTPUT TRISTATE ;
    PORT
      LAYER met3 ;
        RECT 0.000 2382.760 4.000 2383.360 ;
    END
  END la_data_out[11]
  PIN la_data_out[120]
    DIRECTION OUTPUT TRISTATE ;
    PORT
      LAYER met2 ;
        RECT 926.530 3696.000 926.810 3700.000 ;
    END
  END la_data_out[120]
  PIN la_data_out[121]
    DIRECTION OUTPUT TRISTATE ;
    PORT
      LAYER met2 ;
        RECT 215.370 3696.000 215.650 3700.000 ;
    END
  END la_data_out[121]
  PIN la_data_out[122]
    DIRECTION OUTPUT TRISTATE ;
    PORT
      LAYER met3 ;
        RECT 0.000 1079.880 4.000 1080.480 ;
    END
  END la_data_out[122]
  PIN la_data_out[123]
    DIRECTION OUTPUT TRISTATE ;
    PORT
      LAYER met2 ;
        RECT 967.930 0.000 968.210 4.000 ;
    END
  END la_data_out[123]
  PIN la_data_out[124]
    DIRECTION OUTPUT TRISTATE ;
    PORT
      LAYER met2 ;
        RECT 1807.890 3696.000 1808.170 3700.000 ;
    END
  END la_data_out[124]
  PIN la_data_out[125]
    DIRECTION OUTPUT TRISTATE ;
    PORT
      LAYER met3 ;
        RECT 2696.000 1028.200 2700.000 1028.800 ;
    END
  END la_data_out[125]
  PIN la_data_out[126]
    DIRECTION OUTPUT TRISTATE ;
    PORT
      LAYER met2 ;
        RECT 1476.690 0.000 1476.970 4.000 ;
    END
  END la_data_out[126]
  PIN la_data_out[127]
    DIRECTION OUTPUT TRISTATE ;
    PORT
      LAYER met2 ;
        RECT 2526.410 0.000 2526.690 4.000 ;
    END
  END la_data_out[127]
  PIN la_data_out[12]
    DIRECTION OUTPUT TRISTATE ;
    PORT
      LAYER met2 ;
        RECT 273.330 0.000 273.610 4.000 ;
    END
  END la_data_out[12]
  PIN la_data_out[13]
    DIRECTION OUTPUT TRISTATE ;
    PORT
      LAYER met2 ;
        RECT 1485.890 3696.000 1486.170 3700.000 ;
    END
  END la_data_out[13]
  PIN la_data_out[14]
    DIRECTION OUTPUT TRISTATE ;
    PORT
      LAYER met2 ;
        RECT 1739.810 3696.000 1740.090 3700.000 ;
    END
  END la_data_out[14]
  PIN la_data_out[15]
    DIRECTION OUTPUT TRISTATE ;
    PORT
      LAYER met2 ;
        RECT 1171.250 0.000 1171.530 4.000 ;
    END
  END la_data_out[15]
  PIN la_data_out[16]
    DIRECTION OUTPUT TRISTATE ;
    PORT
      LAYER met3 ;
        RECT 2696.000 102.040 2700.000 102.640 ;
    END
  END la_data_out[16]
  PIN la_data_out[17]
    DIRECTION OUTPUT TRISTATE ;
    PORT
      LAYER met2 ;
        RECT 587.970 3696.000 588.250 3700.000 ;
    END
  END la_data_out[17]
  PIN la_data_out[18]
    DIRECTION OUTPUT TRISTATE ;
    PORT
      LAYER met2 ;
        RECT 2171.290 0.000 2171.570 4.000 ;
    END
  END la_data_out[18]
  PIN la_data_out[19]
    DIRECTION OUTPUT TRISTATE ;
    PORT
      LAYER met3 ;
        RECT 2696.000 2831.560 2700.000 2832.160 ;
    END
  END la_data_out[19]
  PIN la_data_out[1]
    DIRECTION OUTPUT TRISTATE ;
    PORT
      LAYER met2 ;
        RECT 1265.090 3696.000 1265.370 3700.000 ;
    END
  END la_data_out[1]
  PIN la_data_out[20]
    DIRECTION OUTPUT TRISTATE ;
    PORT
      LAYER met3 ;
        RECT 2696.000 3132.120 2700.000 3132.720 ;
    END
  END la_data_out[20]
  PIN la_data_out[21]
    DIRECTION OUTPUT TRISTATE ;
    PORT
      LAYER met2 ;
        RECT 622.010 3696.000 622.290 3700.000 ;
    END
  END la_data_out[21]
  PIN la_data_out[22]
    DIRECTION OUTPUT TRISTATE ;
    PORT
      LAYER met3 ;
        RECT 0.000 2282.120 4.000 2282.720 ;
    END
  END la_data_out[22]
  PIN la_data_out[23]
    DIRECTION OUTPUT TRISTATE ;
    PORT
      LAYER met3 ;
        RECT 2696.000 1379.080 2700.000 1379.680 ;
    END
  END la_data_out[23]
  PIN la_data_out[24]
    DIRECTION OUTPUT TRISTATE ;
    PORT
      LAYER met3 ;
        RECT 0.000 1681.000 4.000 1681.600 ;
    END
  END la_data_out[24]
  PIN la_data_out[25]
    DIRECTION OUTPUT TRISTATE ;
    PORT
      LAYER met3 ;
        RECT 2696.000 3257.240 2700.000 3257.840 ;
    END
  END la_data_out[25]
  PIN la_data_out[26]
    DIRECTION OUTPUT TRISTATE ;
    PORT
      LAYER met3 ;
        RECT 2696.000 2256.280 2700.000 2256.880 ;
    END
  END la_data_out[26]
  PIN la_data_out[27]
    DIRECTION OUTPUT TRISTATE ;
    PORT
      LAYER met3 ;
        RECT 0.000 2307.960 4.000 2308.560 ;
    END
  END la_data_out[27]
  PIN la_data_out[28]
    DIRECTION OUTPUT TRISTATE ;
    PORT
      LAYER met3 ;
        RECT 2696.000 1629.320 2700.000 1629.920 ;
    END
  END la_data_out[28]
  PIN la_data_out[29]
    DIRECTION OUTPUT TRISTATE ;
    PORT
      LAYER met2 ;
        RECT 510.690 0.000 510.970 4.000 ;
    END
  END la_data_out[29]
  PIN la_data_out[2]
    DIRECTION OUTPUT TRISTATE ;
    PORT
      LAYER met3 ;
        RECT 2696.000 1604.840 2700.000 1605.440 ;
    END
  END la_data_out[2]
  PIN la_data_out[30]
    DIRECTION OUTPUT TRISTATE ;
    PORT
      LAYER met3 ;
        RECT 0.000 2332.440 4.000 2333.040 ;
    END
  END la_data_out[30]
  PIN la_data_out[31]
    DIRECTION OUTPUT TRISTATE ;
    PORT
      LAYER met3 ;
        RECT 0.000 254.360 4.000 254.960 ;
    END
  END la_data_out[31]
  PIN la_data_out[32]
    DIRECTION OUTPUT TRISTATE ;
    PORT
      LAYER met2 ;
        RECT 1993.730 3696.000 1994.010 3700.000 ;
    END
  END la_data_out[32]
  PIN la_data_out[33]
    DIRECTION OUTPUT TRISTATE ;
    PORT
      LAYER met3 ;
        RECT 2696.000 402.600 2700.000 403.200 ;
    END
  END la_data_out[33]
  PIN la_data_out[34]
    DIRECTION OUTPUT TRISTATE ;
    PORT
      LAYER met3 ;
        RECT 2696.000 1179.160 2700.000 1179.760 ;
    END
  END la_data_out[34]
  PIN la_data_out[35]
    DIRECTION OUTPUT TRISTATE ;
    PORT
      LAYER met3 ;
        RECT 2696.000 828.280 2700.000 828.880 ;
    END
  END la_data_out[35]
  PIN la_data_out[36]
    DIRECTION OUTPUT TRISTATE ;
    PORT
      LAYER met2 ;
        RECT 1527.290 0.000 1527.570 4.000 ;
    END
  END la_data_out[36]
  PIN la_data_out[37]
    DIRECTION OUTPUT TRISTATE ;
    PORT
      LAYER met3 ;
        RECT 2696.000 2656.120 2700.000 2656.720 ;
    END
  END la_data_out[37]
  PIN la_data_out[38]
    DIRECTION OUTPUT TRISTATE ;
    PORT
      LAYER met2 ;
        RECT 130.730 3696.000 131.010 3700.000 ;
    END
  END la_data_out[38]
  PIN la_data_out[39]
    DIRECTION OUTPUT TRISTATE ;
    PORT
      LAYER met3 ;
        RECT 0.000 3359.240 4.000 3359.840 ;
    END
  END la_data_out[39]
  PIN la_data_out[3]
    DIRECTION OUTPUT TRISTATE ;
    PORT
      LAYER met2 ;
        RECT 1205.290 0.000 1205.570 4.000 ;
    END
  END la_data_out[3]
  PIN la_data_out[40]
    DIRECTION OUTPUT TRISTATE ;
    PORT
      LAYER met2 ;
        RECT 2095.850 3696.000 2096.130 3700.000 ;
    END
  END la_data_out[40]
  PIN la_data_out[41]
    DIRECTION OUTPUT TRISTATE ;
    PORT
      LAYER met2 ;
        RECT 1909.090 3696.000 1909.370 3700.000 ;
    END
  END la_data_out[41]
  PIN la_data_out[42]
    DIRECTION OUTPUT TRISTATE ;
    PORT
      LAYER met3 ;
        RECT 2696.000 2280.760 2700.000 2281.360 ;
    END
  END la_data_out[42]
  PIN la_data_out[43]
    DIRECTION OUTPUT TRISTATE ;
    PORT
      LAYER met2 ;
        RECT 825.330 3696.000 825.610 3700.000 ;
    END
  END la_data_out[43]
  PIN la_data_out[44]
    DIRECTION OUTPUT TRISTATE ;
    PORT
      LAYER met2 ;
        RECT 985.410 0.000 985.690 4.000 ;
    END
  END la_data_out[44]
  PIN la_data_out[45]
    DIRECTION OUTPUT TRISTATE ;
    PORT
      LAYER met3 ;
        RECT 0.000 1430.760 4.000 1431.360 ;
    END
  END la_data_out[45]
  PIN la_data_out[46]
    DIRECTION OUTPUT TRISTATE ;
    PORT
      LAYER met2 ;
        RECT 1282.570 3696.000 1282.850 3700.000 ;
    END
  END la_data_out[46]
  PIN la_data_out[47]
    DIRECTION OUTPUT TRISTATE ;
    PORT
      LAYER met2 ;
        RECT 2671.770 3696.000 2672.050 3700.000 ;
    END
  END la_data_out[47]
  PIN la_data_out[48]
    DIRECTION OUTPUT TRISTATE ;
    PORT
      LAYER met2 ;
        RECT 249.410 3696.000 249.690 3700.000 ;
    END
  END la_data_out[48]
  PIN la_data_out[49]
    DIRECTION OUTPUT TRISTATE ;
    PORT
      LAYER met2 ;
        RECT 1509.810 0.000 1510.090 4.000 ;
    END
  END la_data_out[49]
  PIN la_data_out[4]
    DIRECTION OUTPUT TRISTATE ;
    PORT
      LAYER met3 ;
        RECT 0.000 554.920 4.000 555.520 ;
    END
  END la_data_out[4]
  PIN la_data_out[50]
    DIRECTION OUTPUT TRISTATE ;
    PORT
      LAYER met3 ;
        RECT 0.000 1406.280 4.000 1406.880 ;
    END
  END la_data_out[50]
  PIN la_data_out[51]
    DIRECTION OUTPUT TRISTATE ;
    PORT
      LAYER met3 ;
        RECT 0.000 3083.160 4.000 3083.760 ;
    END
  END la_data_out[51]
  PIN la_data_out[52]
    DIRECTION OUTPUT TRISTATE ;
    PORT
      LAYER met2 ;
        RECT 1239.330 0.000 1239.610 4.000 ;
    END
  END la_data_out[52]
  PIN la_data_out[53]
    DIRECTION OUTPUT TRISTATE ;
    PORT
      LAYER met3 ;
        RECT 2696.000 3057.320 2700.000 3057.920 ;
    END
  END la_data_out[53]
  PIN la_data_out[54]
    DIRECTION OUTPUT TRISTATE ;
    PORT
      LAYER met3 ;
        RECT 0.000 805.160 4.000 805.760 ;
    END
  END la_data_out[54]
  PIN la_data_out[55]
    DIRECTION OUTPUT TRISTATE ;
    PORT
      LAYER met2 ;
        RECT 2248.570 3696.000 2248.850 3700.000 ;
    END
  END la_data_out[55]
  PIN la_data_out[56]
    DIRECTION OUTPUT TRISTATE ;
    PORT
      LAYER met2 ;
        RECT 1689.210 3696.000 1689.490 3700.000 ;
    END
  END la_data_out[56]
  PIN la_data_out[57]
    DIRECTION OUTPUT TRISTATE ;
    PORT
      LAYER met3 ;
        RECT 2696.000 1429.400 2700.000 1430.000 ;
    END
  END la_data_out[57]
  PIN la_data_out[58]
    DIRECTION OUTPUT TRISTATE ;
    PORT
      LAYER met2 ;
        RECT 1358.010 0.000 1358.290 4.000 ;
    END
  END la_data_out[58]
  PIN la_data_out[59]
    DIRECTION OUTPUT TRISTATE ;
    PORT
      LAYER met3 ;
        RECT 0.000 829.640 4.000 830.240 ;
    END
  END la_data_out[59]
  PIN la_data_out[5]
    DIRECTION OUTPUT TRISTATE ;
    PORT
      LAYER met3 ;
        RECT 2696.000 2881.880 2700.000 2882.480 ;
    END
  END la_data_out[5]
  PIN la_data_out[60]
    DIRECTION OUTPUT TRISTATE ;
    PORT
      LAYER met3 ;
        RECT 2696.000 152.360 2700.000 152.960 ;
    END
  END la_data_out[60]
  PIN la_data_out[61]
    DIRECTION OUTPUT TRISTATE ;
    PORT
      LAYER met2 ;
        RECT 1553.970 3696.000 1554.250 3700.000 ;
    END
  END la_data_out[61]
  PIN la_data_out[62]
    DIRECTION OUTPUT TRISTATE ;
    PORT
      LAYER met3 ;
        RECT 2696.000 1980.200 2700.000 1980.800 ;
    END
  END la_data_out[62]
  PIN la_data_out[63]
    DIRECTION OUTPUT TRISTATE ;
    PORT
      LAYER met2 ;
        RECT 832.690 0.000 832.970 4.000 ;
    END
  END la_data_out[63]
  PIN la_data_out[64]
    DIRECTION OUTPUT TRISTATE ;
    PORT
      LAYER met2 ;
        RECT 2045.250 3696.000 2045.530 3700.000 ;
    END
  END la_data_out[64]
  PIN la_data_out[65]
    DIRECTION OUTPUT TRISTATE ;
    PORT
      LAYER met3 ;
        RECT 0.000 303.320 4.000 303.920 ;
    END
  END la_data_out[65]
  PIN la_data_out[66]
    DIRECTION OUTPUT TRISTATE ;
    PORT
      LAYER met2 ;
        RECT 1984.530 0.000 1984.810 4.000 ;
    END
  END la_data_out[66]
  PIN la_data_out[67]
    DIRECTION OUTPUT TRISTATE ;
    PORT
      LAYER met2 ;
        RECT 1018.530 0.000 1018.810 4.000 ;
    END
  END la_data_out[67]
  PIN la_data_out[68]
    DIRECTION OUTPUT TRISTATE ;
    PORT
      LAYER met2 ;
        RECT 2035.130 0.000 2035.410 4.000 ;
    END
  END la_data_out[68]
  PIN la_data_out[69]
    DIRECTION OUTPUT TRISTATE ;
    PORT
      LAYER met2 ;
        RECT 2306.530 0.000 2306.810 4.000 ;
    END
  END la_data_out[69]
  PIN la_data_out[6]
    DIRECTION OUTPUT TRISTATE ;
    PORT
      LAYER met2 ;
        RECT 1214.490 3696.000 1214.770 3700.000 ;
    END
  END la_data_out[6]
  PIN la_data_out[70]
    DIRECTION OUTPUT TRISTATE ;
    PORT
      LAYER met3 ;
        RECT 0.000 53.080 4.000 53.680 ;
    END
  END la_data_out[70]
  PIN la_data_out[71]
    DIRECTION OUTPUT TRISTATE ;
    PORT
      LAYER met3 ;
        RECT 2696.000 2030.520 2700.000 2031.120 ;
    END
  END la_data_out[71]
  PIN la_data_out[72]
    DIRECTION OUTPUT TRISTATE ;
    PORT
      LAYER met2 ;
        RECT 2594.490 0.000 2594.770 4.000 ;
    END
  END la_data_out[72]
  PIN la_data_out[73]
    DIRECTION OUTPUT TRISTATE ;
    PORT
      LAYER met3 ;
        RECT 2696.000 552.200 2700.000 552.800 ;
    END
  END la_data_out[73]
  PIN la_data_out[74]
    DIRECTION OUTPUT TRISTATE ;
    PORT
      LAYER met3 ;
        RECT 2696.000 126.520 2700.000 127.120 ;
    END
  END la_data_out[74]
  PIN la_data_out[75]
    DIRECTION OUTPUT TRISTATE ;
    PORT
      LAYER met2 ;
        RECT 773.810 3696.000 774.090 3700.000 ;
    END
  END la_data_out[75]
  PIN la_data_out[76]
    DIRECTION OUTPUT TRISTATE ;
    PORT
      LAYER met2 ;
        RECT 2603.690 3696.000 2603.970 3700.000 ;
    END
  END la_data_out[76]
  PIN la_data_out[77]
    DIRECTION OUTPUT TRISTATE ;
    PORT
      LAYER met2 ;
        RECT 1255.890 0.000 1256.170 4.000 ;
    END
  END la_data_out[77]
  PIN la_data_out[78]
    DIRECTION OUTPUT TRISTATE ;
    PORT
      LAYER met2 ;
        RECT 2425.210 0.000 2425.490 4.000 ;
    END
  END la_data_out[78]
  PIN la_data_out[79]
    DIRECTION OUTPUT TRISTATE ;
    PORT
      LAYER met2 ;
        RECT 120.610 0.000 120.890 4.000 ;
    END
  END la_data_out[79]
  PIN la_data_out[7]
    DIRECTION OUTPUT TRISTATE ;
    PORT
      LAYER met3 ;
        RECT 2696.000 1229.480 2700.000 1230.080 ;
    END
  END la_data_out[7]
  PIN la_data_out[80]
    DIRECTION OUTPUT TRISTATE ;
    PORT
      LAYER met3 ;
        RECT 0.000 654.200 4.000 654.800 ;
    END
  END la_data_out[80]
  PIN la_data_out[81]
    DIRECTION OUTPUT TRISTATE ;
    PORT
      LAYER met2 ;
        RECT 1001.970 0.000 1002.250 4.000 ;
    END
  END la_data_out[81]
  PIN la_data_out[82]
    DIRECTION OUTPUT TRISTATE ;
    PORT
      LAYER met2 ;
        RECT 1865.850 0.000 1866.130 4.000 ;
    END
  END la_data_out[82]
  PIN la_data_out[83]
    DIRECTION OUTPUT TRISTATE ;
    PORT
      LAYER met2 ;
        RECT 2146.450 3696.000 2146.730 3700.000 ;
    END
  END la_data_out[83]
  PIN la_data_out[84]
    DIRECTION OUTPUT TRISTATE ;
    PORT
      LAYER met3 ;
        RECT 0.000 1831.960 4.000 1832.560 ;
    END
  END la_data_out[84]
  PIN la_data_out[85]
    DIRECTION OUTPUT TRISTATE ;
    PORT
      LAYER met3 ;
        RECT 2696.000 2105.320 2700.000 2105.920 ;
    END
  END la_data_out[85]
  PIN la_data_out[86]
    DIRECTION OUTPUT TRISTATE ;
    PORT
      LAYER met2 ;
        RECT 1899.890 0.000 1900.170 4.000 ;
    END
  END la_data_out[86]
  PIN la_data_out[87]
    DIRECTION OUTPUT TRISTATE ;
    PORT
      LAYER met3 ;
        RECT 0.000 2683.320 4.000 2683.920 ;
    END
  END la_data_out[87]
  PIN la_data_out[88]
    DIRECTION OUTPUT TRISTATE ;
    PORT
      LAYER met2 ;
        RECT 2119.770 0.000 2120.050 4.000 ;
    END
  END la_data_out[88]
  PIN la_data_out[89]
    DIRECTION OUTPUT TRISTATE ;
    PORT
      LAYER met3 ;
        RECT 0.000 178.200 4.000 178.800 ;
    END
  END la_data_out[89]
  PIN la_data_out[8]
    DIRECTION OUTPUT TRISTATE ;
    PORT
      LAYER met3 ;
        RECT 0.000 3159.320 4.000 3159.920 ;
    END
  END la_data_out[8]
  PIN la_data_out[90]
    DIRECTION OUTPUT TRISTATE ;
    PORT
      LAYER met3 ;
        RECT 0.000 3308.920 4.000 3309.520 ;
    END
  END la_data_out[90]
  PIN la_data_out[91]
    DIRECTION OUTPUT TRISTATE ;
    PORT
      LAYER met3 ;
        RECT 0.000 603.880 4.000 604.480 ;
    END
  END la_data_out[91]
  PIN la_data_out[92]
    DIRECTION OUTPUT TRISTATE ;
    PORT
      LAYER met3 ;
        RECT 2696.000 1879.560 2700.000 1880.160 ;
    END
  END la_data_out[92]
  PIN la_data_out[93]
    DIRECTION OUTPUT TRISTATE ;
    PORT
      LAYER met2 ;
        RECT 841.890 3696.000 842.170 3700.000 ;
    END
  END la_data_out[93]
  PIN la_data_out[94]
    DIRECTION OUTPUT TRISTATE ;
    PORT
      LAYER met3 ;
        RECT 2696.000 1830.600 2700.000 1831.200 ;
    END
  END la_data_out[94]
  PIN la_data_out[95]
    DIRECTION OUTPUT TRISTATE ;
    PORT
      LAYER met3 ;
        RECT 2696.000 202.680 2700.000 203.280 ;
    END
  END la_data_out[95]
  PIN la_data_out[96]
    DIRECTION OUTPUT TRISTATE ;
    PORT
      LAYER met2 ;
        RECT 231.930 3696.000 232.210 3700.000 ;
    END
  END la_data_out[96]
  PIN la_data_out[97]
    DIRECTION OUTPUT TRISTATE ;
    PORT
      LAYER met2 ;
        RECT 87.490 0.000 87.770 4.000 ;
    END
  END la_data_out[97]
  PIN la_data_out[98]
    DIRECTION OUTPUT TRISTATE ;
    PORT
      LAYER met2 ;
        RECT 2519.050 3696.000 2519.330 3700.000 ;
    END
  END la_data_out[98]
  PIN la_data_out[99]
    DIRECTION OUTPUT TRISTATE ;
    PORT
      LAYER met2 ;
        RECT 2417.850 3696.000 2418.130 3700.000 ;
    END
  END la_data_out[99]
  PIN la_data_out[9]
    DIRECTION OUTPUT TRISTATE ;
    PORT
      LAYER met3 ;
        RECT 0.000 3510.200 4.000 3510.800 ;
    END
  END la_data_out[9]
  PIN la_oen[0]
    DIRECTION INPUT ;
    PORT
      LAYER met3 ;
        RECT 0.000 2633.000 4.000 2633.600 ;
    END
  END la_oen[0]
  PIN la_oen[100]
    DIRECTION INPUT ;
    PORT
      LAYER met3 ;
        RECT 2696.000 2807.080 2700.000 2807.680 ;
    END
  END la_oen[100]
  PIN la_oen[101]
    DIRECTION INPUT ;
    PORT
      LAYER met2 ;
        RECT 1248.530 3696.000 1248.810 3700.000 ;
    END
  END la_oen[101]
  PIN la_oen[102]
    DIRECTION INPUT ;
    PORT
      LAYER met2 ;
        RECT 1052.570 0.000 1052.850 4.000 ;
    END
  END la_oen[102]
  PIN la_oen[103]
    DIRECTION INPUT ;
    PORT
      LAYER met2 ;
        RECT 1137.210 0.000 1137.490 4.000 ;
    END
  END la_oen[103]
  PIN la_oen[104]
    DIRECTION INPUT ;
    PORT
      LAYER met3 ;
        RECT 2696.000 2180.120 2700.000 2180.720 ;
    END
  END la_oen[104]
  PIN la_oen[105]
    DIRECTION INPUT ;
    PORT
      LAYER met3 ;
        RECT 2696.000 1705.480 2700.000 1706.080 ;
    END
  END la_oen[105]
  PIN la_oen[106]
    DIRECTION INPUT ;
    PORT
      LAYER met2 ;
        RECT 104.050 0.000 104.330 4.000 ;
    END
  END la_oen[106]
  PIN la_oen[107]
    DIRECTION INPUT ;
    PORT
      LAYER met2 ;
        RECT 1306.490 0.000 1306.770 4.000 ;
    END
  END la_oen[107]
  PIN la_oen[108]
    DIRECTION INPUT ;
    PORT
      LAYER met3 ;
        RECT 2696.000 2956.680 2700.000 2957.280 ;
    END
  END la_oen[108]
  PIN la_oen[109]
    DIRECTION INPUT ;
    PORT
      LAYER met2 ;
        RECT 1095.810 3696.000 1096.090 3700.000 ;
    END
  END la_oen[109]
  PIN la_oen[10]
    DIRECTION INPUT ;
    PORT
      LAYER met3 ;
        RECT 2696.000 2456.200 2700.000 2456.800 ;
    END
  END la_oen[10]
  PIN la_oen[110]
    DIRECTION INPUT ;
    PORT
      LAYER met2 ;
        RECT 1113.290 3696.000 1113.570 3700.000 ;
    END
  END la_oen[110]
  PIN la_oen[111]
    DIRECTION INPUT ;
    PORT
      LAYER met2 ;
        RECT 1858.490 3696.000 1858.770 3700.000 ;
    END
  END la_oen[111]
  PIN la_oen[112]
    DIRECTION INPUT ;
    PORT
      LAYER met2 ;
        RECT 2001.090 0.000 2001.370 4.000 ;
    END
  END la_oen[112]
  PIN la_oen[113]
    DIRECTION INPUT ;
    PORT
      LAYER met2 ;
        RECT 1374.570 0.000 1374.850 4.000 ;
    END
  END la_oen[113]
  PIN la_oen[114]
    DIRECTION INPUT ;
    PORT
      LAYER met3 ;
        RECT 0.000 3109.000 4.000 3109.600 ;
    END
  END la_oen[114]
  PIN la_oen[115]
    DIRECTION INPUT ;
    PORT
      LAYER met3 ;
        RECT 0.000 429.800 4.000 430.400 ;
    END
  END la_oen[115]
  PIN la_oen[116]
    DIRECTION INPUT ;
    PORT
      LAYER met2 ;
        RECT 740.690 3696.000 740.970 3700.000 ;
    END
  END la_oen[116]
  PIN la_oen[117]
    DIRECTION INPUT ;
    PORT
      LAYER met2 ;
        RECT 1383.770 3696.000 1384.050 3700.000 ;
    END
  END la_oen[117]
  PIN la_oen[118]
    DIRECTION INPUT ;
    PORT
      LAYER met3 ;
        RECT 2696.000 1253.960 2700.000 1254.560 ;
    END
  END la_oen[118]
  PIN la_oen[119]
    DIRECTION INPUT ;
    PORT
      LAYER met3 ;
        RECT 0.000 1281.160 4.000 1281.760 ;
    END
  END la_oen[119]
  PIN la_oen[11]
    DIRECTION INPUT ;
    PORT
      LAYER met2 ;
        RECT 570.490 3696.000 570.770 3700.000 ;
    END
  END la_oen[11]
  PIN la_oen[120]
    DIRECTION INPUT ;
    PORT
      LAYER met2 ;
        RECT 1773.850 3696.000 1774.130 3700.000 ;
    END
  END la_oen[120]
  PIN la_oen[121]
    DIRECTION INPUT ;
    PORT
      LAYER met3 ;
        RECT 0.000 629.720 4.000 630.320 ;
    END
  END la_oen[121]
  PIN la_oen[122]
    DIRECTION INPUT ;
    PORT
      LAYER met3 ;
        RECT 2696.000 602.520 2700.000 603.120 ;
    END
  END la_oen[122]
  PIN la_oen[123]
    DIRECTION INPUT ;
    PORT
      LAYER met3 ;
        RECT 0.000 103.400 4.000 104.000 ;
    END
  END la_oen[123]
  PIN la_oen[124]
    DIRECTION INPUT ;
    PORT
      LAYER met3 ;
        RECT 2696.000 277.480 2700.000 278.080 ;
    END
  END la_oen[124]
  PIN la_oen[125]
    DIRECTION INPUT ;
    PORT
      LAYER met3 ;
        RECT 2696.000 3557.800 2700.000 3558.400 ;
    END
  END la_oen[125]
  PIN la_oen[126]
    DIRECTION INPUT ;
    PORT
      LAYER met3 ;
        RECT 2696.000 852.760 2700.000 853.360 ;
    END
  END la_oen[126]
  PIN la_oen[127]
    DIRECTION INPUT ;
    PORT
      LAYER met2 ;
        RECT 426.050 0.000 426.330 4.000 ;
    END
  END la_oen[127]
  PIN la_oen[12]
    DIRECTION INPUT ;
    PORT
      LAYER met3 ;
        RECT 0.000 1380.440 4.000 1381.040 ;
    END
  END la_oen[12]
  PIN la_oen[13]
    DIRECTION INPUT ;
    PORT
      LAYER met2 ;
        RECT 2180.490 3696.000 2180.770 3700.000 ;
    END
  END la_oen[13]
  PIN la_oen[14]
    DIRECTION INPUT ;
    PORT
      LAYER met2 ;
        RECT 2475.810 0.000 2476.090 4.000 ;
    END
  END la_oen[14]
  PIN la_oen[15]
    DIRECTION INPUT ;
    PORT
      LAYER met3 ;
        RECT 2696.000 1279.800 2700.000 1280.400 ;
    END
  END la_oen[15]
  PIN la_oen[16]
    DIRECTION INPUT ;
    PORT
      LAYER met3 ;
        RECT 2696.000 1404.920 2700.000 1405.520 ;
    END
  END la_oen[16]
  PIN la_oen[17]
    DIRECTION INPUT ;
    PORT
      LAYER met3 ;
        RECT 2696.000 2756.760 2700.000 2757.360 ;
    END
  END la_oen[17]
  PIN la_oen[18]
    DIRECTION INPUT ;
    PORT
      LAYER met2 ;
        RECT 1502.450 3696.000 1502.730 3700.000 ;
    END
  END la_oen[18]
  PIN la_oen[19]
    DIRECTION INPUT ;
    PORT
      LAYER met3 ;
        RECT 0.000 680.040 4.000 680.640 ;
    END
  END la_oen[19]
  PIN la_oen[1]
    DIRECTION INPUT ;
    PORT
      LAYER met3 ;
        RECT 0.000 2031.880 4.000 2032.480 ;
    END
  END la_oen[1]
  PIN la_oen[20]
    DIRECTION INPUT ;
    PORT
      LAYER met2 ;
        RECT 1323.970 0.000 1324.250 4.000 ;
    END
  END la_oen[20]
  PIN la_oen[21]
    DIRECTION INPUT ;
    PORT
      LAYER met3 ;
        RECT 2696.000 2080.840 2700.000 2081.440 ;
    END
  END la_oen[21]
  PIN la_oen[22]
    DIRECTION INPUT ;
    PORT
      LAYER met2 ;
        RECT 1451.850 3696.000 1452.130 3700.000 ;
    END
  END la_oen[22]
  PIN la_oen[23]
    DIRECTION INPUT ;
    PORT
      LAYER met3 ;
        RECT 2696.000 953.400 2700.000 954.000 ;
    END
  END la_oen[23]
  PIN la_oen[24]
    DIRECTION INPUT ;
    PORT
      LAYER met3 ;
        RECT 0.000 2582.680 4.000 2583.280 ;
    END
  END la_oen[24]
  PIN la_oen[25]
    DIRECTION INPUT ;
    PORT
      LAYER met3 ;
        RECT 2696.000 2631.640 2700.000 2632.240 ;
    END
  END la_oen[25]
  PIN la_oen[26]
    DIRECTION INPUT ;
    PORT
      LAYER met2 ;
        RECT 1289.930 0.000 1290.210 4.000 ;
    END
  END la_oen[26]
  PIN la_oen[27]
    DIRECTION INPUT ;
    PORT
      LAYER met2 ;
        RECT 849.250 0.000 849.530 4.000 ;
    END
  END la_oen[27]
  PIN la_oen[28]
    DIRECTION INPUT ;
    PORT
      LAYER met3 ;
        RECT 2696.000 503.240 2700.000 503.840 ;
    END
  END la_oen[28]
  PIN la_oen[29]
    DIRECTION INPUT ;
    PORT
      LAYER met2 ;
        RECT 1561.330 0.000 1561.610 4.000 ;
    END
  END la_oen[29]
  PIN la_oen[2]
    DIRECTION INPUT ;
    PORT
      LAYER met3 ;
        RECT 2696.000 777.960 2700.000 778.560 ;
    END
  END la_oen[2]
  PIN la_oen[30]
    DIRECTION INPUT ;
    PORT
      LAYER met2 ;
        RECT 1577.890 0.000 1578.170 4.000 ;
    END
  END la_oen[30]
  PIN la_oen[31]
    DIRECTION INPUT ;
    PORT
      LAYER met2 ;
        RECT 2085.730 0.000 2086.010 4.000 ;
    END
  END la_oen[31]
  PIN la_oen[32]
    DIRECTION INPUT ;
    PORT
      LAYER met2 ;
        RECT 19.410 0.000 19.690 4.000 ;
    END
  END la_oen[32]
  PIN la_oen[33]
    DIRECTION INPUT ;
    PORT
      LAYER met2 ;
        RECT 2611.050 0.000 2611.330 4.000 ;
    END
  END la_oen[33]
  PIN la_oen[34]
    DIRECTION INPUT ;
    PORT
      LAYER met3 ;
        RECT 2696.000 378.120 2700.000 378.720 ;
    END
  END la_oen[34]
  PIN la_oen[35]
    DIRECTION INPUT ;
    PORT
      LAYER met2 ;
        RECT 435.250 3696.000 435.530 3700.000 ;
    END
  END la_oen[35]
  PIN la_oen[36]
    DIRECTION INPUT ;
    PORT
      LAYER met2 ;
        RECT 197.890 3696.000 198.170 3700.000 ;
    END
  END la_oen[36]
  PIN la_oen[37]
    DIRECTION INPUT ;
    PORT
      LAYER met3 ;
        RECT 0.000 3534.680 4.000 3535.280 ;
    END
  END la_oen[37]
  PIN la_oen[38]
    DIRECTION INPUT ;
    PORT
      LAYER met3 ;
        RECT 0.000 2457.560 4.000 2458.160 ;
    END
  END la_oen[38]
  PIN la_oen[39]
    DIRECTION INPUT ;
    PORT
      LAYER met3 ;
        RECT 0.000 1781.640 4.000 1782.240 ;
    END
  END la_oen[39]
  PIN la_oen[3]
    DIRECTION INPUT ;
    PORT
      LAYER met3 ;
        RECT 2696.000 2681.960 2700.000 2682.560 ;
    END
  END la_oen[3]
  PIN la_oen[40]
    DIRECTION INPUT ;
    PORT
      LAYER met3 ;
        RECT 2696.000 3157.960 2700.000 3158.560 ;
    END
  END la_oen[40]
  PIN la_oen[41]
    DIRECTION INPUT ;
    PORT
      LAYER met2 ;
        RECT 2349.770 3696.000 2350.050 3700.000 ;
    END
  END la_oen[41]
  PIN la_oen[42]
    DIRECTION INPUT ;
    PORT
      LAYER met3 ;
        RECT 2696.000 2732.280 2700.000 2732.880 ;
    END
  END la_oen[42]
  PIN la_oen[43]
    DIRECTION INPUT ;
    PORT
      LAYER met3 ;
        RECT 0.000 3284.440 4.000 3285.040 ;
    END
  END la_oen[43]
  PIN la_oen[44]
    DIRECTION INPUT ;
    PORT
      LAYER met3 ;
        RECT 2696.000 652.840 2700.000 653.440 ;
    END
  END la_oen[44]
  PIN la_oen[45]
    DIRECTION INPUT ;
    PORT
      LAYER met2 ;
        RECT 2265.130 3696.000 2265.410 3700.000 ;
    END
  END la_oen[45]
  PIN la_oen[46]
    DIRECTION INPUT ;
    PORT
      LAYER met3 ;
        RECT 2696.000 2531.000 2700.000 2531.600 ;
    END
  END la_oen[46]
  PIN la_oen[47]
    DIRECTION INPUT ;
    PORT
      LAYER met3 ;
        RECT 2696.000 1453.880 2700.000 1454.480 ;
    END
  END la_oen[47]
  PIN la_oen[48]
    DIRECTION INPUT ;
    PORT
      LAYER met2 ;
        RECT 1333.170 3696.000 1333.450 3700.000 ;
    END
  END la_oen[48]
  PIN la_oen[49]
    DIRECTION INPUT ;
    PORT
      LAYER met2 ;
        RECT 1536.490 3696.000 1536.770 3700.000 ;
    END
  END la_oen[49]
  PIN la_oen[4]
    DIRECTION INPUT ;
    PORT
      LAYER met2 ;
        RECT 859.370 3696.000 859.650 3700.000 ;
    END
  END la_oen[4]
  PIN la_oen[50]
    DIRECTION INPUT ;
    PORT
      LAYER met2 ;
        RECT 2197.050 3696.000 2197.330 3700.000 ;
    END
  END la_oen[50]
  PIN la_oen[51]
    DIRECTION INPUT ;
    PORT
      LAYER met2 ;
        RECT 1408.610 0.000 1408.890 4.000 ;
    END
  END la_oen[51]
  PIN la_oen[52]
    DIRECTION INPUT ;
    PORT
      LAYER met3 ;
        RECT 2696.000 2355.560 2700.000 2356.160 ;
    END
  END la_oen[52]
  PIN la_oen[53]
    DIRECTION INPUT ;
    PORT
      LAYER met2 ;
        RECT 334.050 3696.000 334.330 3700.000 ;
    END
  END la_oen[53]
  PIN la_oen[54]
    DIRECTION INPUT ;
    PORT
      LAYER met2 ;
        RECT 2637.730 3696.000 2638.010 3700.000 ;
    END
  END la_oen[54]
  PIN la_oen[55]
    DIRECTION INPUT ;
    PORT
      LAYER met2 ;
        RECT 282.530 3696.000 282.810 3700.000 ;
    END
  END la_oen[55]
  PIN la_oen[56]
    DIRECTION INPUT ;
    PORT
      LAYER met2 ;
        RECT 1926.570 3696.000 1926.850 3700.000 ;
    END
  END la_oen[56]
  PIN la_oen[57]
    DIRECTION INPUT ;
    PORT
      LAYER met3 ;
        RECT 0.000 2858.760 4.000 2859.360 ;
    END
  END la_oen[57]
  PIN la_oen[58]
    DIRECTION INPUT ;
    PORT
      LAYER met3 ;
        RECT 0.000 1555.880 4.000 1556.480 ;
    END
  END la_oen[58]
  PIN la_oen[59]
    DIRECTION INPUT ;
    PORT
      LAYER met3 ;
        RECT 2696.000 3032.840 2700.000 3033.440 ;
    END
  END la_oen[59]
  PIN la_oen[5]
    DIRECTION INPUT ;
    PORT
      LAYER met2 ;
        RECT 384.650 3696.000 384.930 3700.000 ;
    END
  END la_oen[5]
  PIN la_oen[60]
    DIRECTION INPUT ;
    PORT
      LAYER met3 ;
        RECT 0.000 2883.240 4.000 2883.840 ;
    END
  END la_oen[60]
  PIN la_oen[61]
    DIRECTION INPUT ;
    PORT
      LAYER met2 ;
        RECT 1197.930 3696.000 1198.210 3700.000 ;
    END
  END la_oen[61]
  PIN la_oen[62]
    DIRECTION INPUT ;
    PORT
      LAYER met2 ;
        RECT 1628.490 0.000 1628.770 4.000 ;
    END
  END la_oen[62]
  PIN la_oen[63]
    DIRECTION INPUT ;
    PORT
      LAYER met3 ;
        RECT 2696.000 1579.000 2700.000 1579.600 ;
    END
  END la_oen[63]
  PIN la_oen[64]
    DIRECTION INPUT ;
    PORT
      LAYER met2 ;
        RECT 2289.050 0.000 2289.330 4.000 ;
    END
  END la_oen[64]
  PIN la_oen[65]
    DIRECTION INPUT ;
    PORT
      LAYER met2 ;
        RECT 696.530 0.000 696.810 4.000 ;
    END
  END la_oen[65]
  PIN la_oen[66]
    DIRECTION INPUT ;
    PORT
      LAYER met2 ;
        RECT 2400.370 3696.000 2400.650 3700.000 ;
    END
  END la_oen[66]
  PIN la_oen[67]
    DIRECTION INPUT ;
    PORT
      LAYER met3 ;
        RECT 0.000 2182.840 4.000 2183.440 ;
    END
  END la_oen[67]
  PIN la_oen[68]
    DIRECTION INPUT ;
    PORT
      LAYER met3 ;
        RECT 0.000 1981.560 4.000 1982.160 ;
    END
  END la_oen[68]
  PIN la_oen[69]
    DIRECTION INPUT ;
    PORT
      LAYER met3 ;
        RECT 2696.000 3206.920 2700.000 3207.520 ;
    END
  END la_oen[69]
  PIN la_oen[6]
    DIRECTION INPUT ;
    PORT
      LAYER met3 ;
        RECT 0.000 954.760 4.000 955.360 ;
    END
  END la_oen[6]
  PIN la_oen[70]
    DIRECTION INPUT ;
    PORT
      LAYER met3 ;
        RECT 0.000 2933.560 4.000 2934.160 ;
    END
  END la_oen[70]
  PIN la_oen[71]
    DIRECTION INPUT ;
    PORT
      LAYER met2 ;
        RECT 1824.450 3696.000 1824.730 3700.000 ;
    END
  END la_oen[71]
  PIN la_oen[72]
    DIRECTION INPUT ;
    PORT
      LAYER met2 ;
        RECT 2315.730 3696.000 2316.010 3700.000 ;
    END
  END la_oen[72]
  PIN la_oen[73]
    DIRECTION INPUT ;
    PORT
      LAYER met3 ;
        RECT 0.000 3058.680 4.000 3059.280 ;
    END
  END la_oen[73]
  PIN la_oen[74]
    DIRECTION INPUT ;
    PORT
      LAYER met3 ;
        RECT 2696.000 1304.280 2700.000 1304.880 ;
    END
  END la_oen[74]
  PIN la_oen[75]
    DIRECTION INPUT ;
    PORT
      LAYER met2 ;
        RECT 883.290 0.000 883.570 4.000 ;
    END
  END la_oen[75]
  PIN la_oen[76]
    DIRECTION INPUT ;
    PORT
      LAYER met2 ;
        RECT 1273.370 0.000 1273.650 4.000 ;
    END
  END la_oen[76]
  PIN la_oen[77]
    DIRECTION INPUT ;
    PORT
      LAYER met2 ;
        RECT 469.290 3696.000 469.570 3700.000 ;
    END
  END la_oen[77]
  PIN la_oen[78]
    DIRECTION INPUT ;
    PORT
      LAYER met2 ;
        RECT 1316.610 3696.000 1316.890 3700.000 ;
    END
  END la_oen[78]
  PIN la_oen[79]
    DIRECTION INPUT ;
    PORT
      LAYER met3 ;
        RECT 2696.000 2506.520 2700.000 2507.120 ;
    END
  END la_oen[79]
  PIN la_oen[7]
    DIRECTION INPUT ;
    PORT
      LAYER met2 ;
        RECT 265.970 3696.000 266.250 3700.000 ;
    END
  END la_oen[7]
  PIN la_oen[80]
    DIRECTION INPUT ;
    PORT
      LAYER met3 ;
        RECT 0.000 3034.200 4.000 3034.800 ;
    END
  END la_oen[80]
  PIN la_oen[81]
    DIRECTION INPUT ;
    PORT
      LAYER met3 ;
        RECT 0.000 3609.480 4.000 3610.080 ;
    END
  END la_oen[81]
  PIN la_oen[82]
    DIRECTION INPUT ;
    PORT
      LAYER met3 ;
        RECT 2696.000 928.920 2700.000 929.520 ;
    END
  END la_oen[82]
  PIN la_oen[83]
    DIRECTION INPUT ;
    PORT
      LAYER met2 ;
        RECT 1570.530 3696.000 1570.810 3700.000 ;
    END
  END la_oen[83]
  PIN la_oen[84]
    DIRECTION INPUT ;
    PORT
      LAYER met3 ;
        RECT 0.000 754.840 4.000 755.440 ;
    END
  END la_oen[84]
  PIN la_oen[85]
    DIRECTION INPUT ;
    PORT
      LAYER met3 ;
        RECT 2696.000 1354.600 2700.000 1355.200 ;
    END
  END la_oen[85]
  PIN la_oen[86]
    DIRECTION INPUT ;
    PORT
      LAYER met3 ;
        RECT 2696.000 2982.520 2700.000 2983.120 ;
    END
  END la_oen[86]
  PIN la_oen[87]
    DIRECTION INPUT ;
    PORT
      LAYER met2 ;
        RECT 2654.290 3696.000 2654.570 3700.000 ;
    END
  END la_oen[87]
  PIN la_oen[88]
    DIRECTION INPUT ;
    PORT
      LAYER met3 ;
        RECT 2696.000 678.680 2700.000 679.280 ;
    END
  END la_oen[88]
  PIN la_oen[89]
    DIRECTION INPUT ;
    PORT
      LAYER met3 ;
        RECT 0.000 2407.240 4.000 2407.840 ;
    END
  END la_oen[89]
  PIN la_oen[8]
    DIRECTION INPUT ;
    PORT
      LAYER met3 ;
        RECT 2696.000 578.040 2700.000 578.640 ;
    END
  END la_oen[8]
  PIN la_oen[90]
    DIRECTION INPUT ;
    PORT
      LAYER met2 ;
        RECT 977.130 3696.000 977.410 3700.000 ;
    END
  END la_oen[90]
  PIN la_oen[91]
    DIRECTION INPUT ;
    PORT
      LAYER met3 ;
        RECT 2696.000 803.800 2700.000 804.400 ;
    END
  END la_oen[91]
  PIN la_oen[92]
    DIRECTION INPUT ;
    PORT
      LAYER met2 ;
        RECT 629.370 0.000 629.650 4.000 ;
    END
  END la_oen[92]
  PIN la_oen[93]
    DIRECTION INPUT ;
    PORT
      LAYER met3 ;
        RECT 0.000 1630.680 4.000 1631.280 ;
    END
  END la_oen[93]
  PIN la_oen[94]
    DIRECTION INPUT ;
    PORT
      LAYER met2 ;
        RECT 2112.410 3696.000 2112.690 3700.000 ;
    END
  END la_oen[94]
  PIN la_oen[95]
    DIRECTION INPUT ;
    PORT
      LAYER met2 ;
        RECT 2560.450 0.000 2560.730 4.000 ;
    END
  END la_oen[95]
  PIN la_oen[96]
    DIRECTION INPUT ;
    PORT
      LAYER met2 ;
        RECT 1723.250 3696.000 1723.530 3700.000 ;
    END
  END la_oen[96]
  PIN la_oen[97]
    DIRECTION INPUT ;
    PORT
      LAYER met2 ;
        RECT 2492.370 0.000 2492.650 4.000 ;
    END
  END la_oen[97]
  PIN la_oen[98]
    DIRECTION INPUT ;
    PORT
      LAYER met3 ;
        RECT 2696.000 452.920 2700.000 453.520 ;
    END
  END la_oen[98]
  PIN la_oen[99]
    DIRECTION INPUT ;
    PORT
      LAYER met3 ;
        RECT 0.000 2231.800 4.000 2232.400 ;
    END
  END la_oen[99]
  PIN la_oen[9]
    DIRECTION INPUT ;
    PORT
      LAYER met2 ;
        RECT 2018.570 0.000 2018.850 4.000 ;
    END
  END la_oen[9]
  PIN user_clock2
    DIRECTION INPUT ;
    PORT
      LAYER met2 ;
        RECT 1103.170 0.000 1103.450 4.000 ;
    END
  END user_clock2
  PIN vccd1
    DIRECTION INOUT ;
    PORT
      LAYER met3 ;
        RECT 0.000 3334.760 4.000 3335.360 ;
    END
  END vccd1
  PIN vccd2
    DIRECTION INOUT ;
    PORT
      LAYER met2 ;
        RECT 994.610 3696.000 994.890 3700.000 ;
    END
  END vccd2
  PIN vdda1
    DIRECTION INOUT ;
    PORT
      LAYER met3 ;
        RECT 0.000 1757.160 4.000 1757.760 ;
    END
  END vdda1
  PIN vdda2
    DIRECTION INOUT ;
    PORT
      LAYER met3 ;
        RECT 2696.000 3182.440 2700.000 3183.040 ;
    END
  END vdda2
  PIN vssa1
    DIRECTION INOUT ;
    PORT
      LAYER met2 ;
        RECT 1713.130 0.000 1713.410 4.000 ;
    END
  END vssa1
  PIN vssa2
    DIRECTION INOUT ;
    PORT
      LAYER met2 ;
        RECT 679.970 0.000 680.250 4.000 ;
    END
  END vssa2
  PIN vssd1
    DIRECTION INOUT ;
    PORT
      LAYER met2 ;
        RECT 1831.810 0.000 1832.090 4.000 ;
    END
  END vssd1
  PIN vssd2
    DIRECTION INOUT ;
    PORT
      LAYER met2 ;
        RECT 96.690 3696.000 96.970 3700.000 ;
    END
  END vssd2
  PIN wb_clk_i
    DIRECTION INPUT ;
    PORT
      LAYER met3 ;
        RECT 0.000 3459.880 4.000 3460.480 ;
    END
  END wb_clk_i
  PIN wb_rst_i
    DIRECTION INPUT ;
    PORT
      LAYER met2 ;
        RECT 1367.210 3696.000 1367.490 3700.000 ;
    END
  END wb_rst_i
  PIN wbs_ack_o
    DIRECTION OUTPUT TRISTATE ;
    PORT
      LAYER met3 ;
        RECT 0.000 3684.280 4.000 3684.880 ;
    END
  END wbs_ack_o
  PIN wbs_adr_i[0]
    DIRECTION INPUT ;
    PORT
      LAYER met2 ;
        RECT 2450.970 3696.000 2451.250 3700.000 ;
    END
  END wbs_adr_i[0]
  PIN wbs_adr_i[10]
    DIRECTION INPUT ;
    PORT
      LAYER met2 ;
        RECT 1790.410 3696.000 1790.690 3700.000 ;
    END
  END wbs_adr_i[10]
  PIN wbs_adr_i[11]
    DIRECTION INPUT ;
    PORT
      LAYER met3 ;
        RECT 2696.000 1203.640 2700.000 1204.240 ;
    END
  END wbs_adr_i[11]
  PIN wbs_adr_i[12]
    DIRECTION INPUT ;
    PORT
      LAYER met2 ;
        RECT 1036.010 0.000 1036.290 4.000 ;
    END
  END wbs_adr_i[12]
  PIN wbs_adr_i[13]
    DIRECTION INPUT ;
    PORT
      LAYER met3 ;
        RECT 0.000 1606.200 4.000 1606.800 ;
    END
  END wbs_adr_i[13]
  PIN wbs_adr_i[14]
    DIRECTION INPUT ;
    PORT
      LAYER met3 ;
        RECT 0.000 1957.080 4.000 1957.680 ;
    END
  END wbs_adr_i[14]
  PIN wbs_adr_i[15]
    DIRECTION INPUT ;
    PORT
      LAYER met3 ;
        RECT 0.000 1355.960 4.000 1356.560 ;
    END
  END wbs_adr_i[15]
  PIN wbs_adr_i[16]
    DIRECTION INPUT ;
    PORT
      LAYER met2 ;
        RECT 1231.970 3696.000 1232.250 3700.000 ;
    END
  END wbs_adr_i[16]
  PIN wbs_adr_i[17]
    DIRECTION INPUT ;
    PORT
      LAYER met2 ;
        RECT 2536.530 3696.000 2536.810 3700.000 ;
    END
  END wbs_adr_i[17]
  PIN wbs_adr_i[18]
    DIRECTION INPUT ;
    PORT
      LAYER met3 ;
        RECT 0.000 2082.200 4.000 2082.800 ;
    END
  END wbs_adr_i[18]
  PIN wbs_adr_i[19]
    DIRECTION INPUT ;
    PORT
      LAYER met3 ;
        RECT 0.000 329.160 4.000 329.760 ;
    END
  END wbs_adr_i[19]
  PIN wbs_adr_i[1]
    DIRECTION INPUT ;
    PORT
      LAYER met3 ;
        RECT 2696.000 628.360 2700.000 628.960 ;
    END
  END wbs_adr_i[1]
  PIN wbs_adr_i[20]
    DIRECTION INPUT ;
    PORT
      LAYER met3 ;
        RECT 2696.000 2605.800 2700.000 2606.400 ;
    END
  END wbs_adr_i[20]
  PIN wbs_adr_i[21]
    DIRECTION INPUT ;
    PORT
      LAYER met2 ;
        RECT 1180.450 3696.000 1180.730 3700.000 ;
    END
  END wbs_adr_i[21]
  PIN wbs_adr_i[22]
    DIRECTION INPUT ;
    PORT
      LAYER met2 ;
        RECT 656.050 3696.000 656.330 3700.000 ;
    END
  END wbs_adr_i[22]
  PIN wbs_adr_i[23]
    DIRECTION INPUT ;
    PORT
      LAYER met3 ;
        RECT 2696.000 2581.320 2700.000 2581.920 ;
    END
  END wbs_adr_i[23]
  PIN wbs_adr_i[24]
    DIRECTION INPUT ;
    PORT
      LAYER met2 ;
        RECT 2137.250 0.000 2137.530 4.000 ;
    END
  END wbs_adr_i[24]
  PIN wbs_adr_i[25]
    DIRECTION INPUT ;
    PORT
      LAYER met2 ;
        RECT 866.730 0.000 867.010 4.000 ;
    END
  END wbs_adr_i[25]
  PIN wbs_adr_i[26]
    DIRECTION INPUT ;
    PORT
      LAYER met3 ;
        RECT 0.000 278.840 4.000 279.440 ;
    END
  END wbs_adr_i[26]
  PIN wbs_adr_i[27]
    DIRECTION INPUT ;
    PORT
      LAYER met2 ;
        RECT 1070.050 0.000 1070.330 4.000 ;
    END
  END wbs_adr_i[27]
  PIN wbs_adr_i[28]
    DIRECTION INPUT ;
    PORT
      LAYER met2 ;
        RECT 1299.130 3696.000 1299.410 3700.000 ;
    END
  END wbs_adr_i[28]
  PIN wbs_adr_i[29]
    DIRECTION INPUT ;
    PORT
      LAYER met2 ;
        RECT 2441.770 0.000 2442.050 4.000 ;
    END
  END wbs_adr_i[29]
  PIN wbs_adr_i[2]
    DIRECTION INPUT ;
    PORT
      LAYER met3 ;
        RECT 2696.000 1554.520 2700.000 1555.120 ;
    END
  END wbs_adr_i[2]
  PIN wbs_adr_i[30]
    DIRECTION INPUT ;
    PORT
      LAYER met3 ;
        RECT 0.000 529.080 4.000 529.680 ;
    END
  END wbs_adr_i[30]
  PIN wbs_adr_i[31]
    DIRECTION INPUT ;
    PORT
      LAYER met2 ;
        RECT 1882.410 0.000 1882.690 4.000 ;
    END
  END wbs_adr_i[31]
  PIN wbs_adr_i[3]
    DIRECTION INPUT ;
    PORT
      LAYER met2 ;
        RECT 1079.250 3696.000 1079.530 3700.000 ;
    END
  END wbs_adr_i[3]
  PIN wbs_adr_i[4]
    DIRECTION INPUT ;
    PORT
      LAYER met2 ;
        RECT 1594.450 0.000 1594.730 4.000 ;
    END
  END wbs_adr_i[4]
  PIN wbs_adr_i[5]
    DIRECTION INPUT ;
    PORT
      LAYER met2 ;
        RECT 1849.290 0.000 1849.570 4.000 ;
    END
  END wbs_adr_i[5]
  PIN wbs_adr_i[6]
    DIRECTION INPUT ;
    PORT
      LAYER met2 ;
        RECT 494.130 0.000 494.410 4.000 ;
    END
  END wbs_adr_i[6]
  PIN wbs_adr_i[7]
    DIRECTION INPUT ;
    PORT
      LAYER met3 ;
        RECT 0.000 930.280 4.000 930.880 ;
    END
  END wbs_adr_i[7]
  PIN wbs_adr_i[8]
    DIRECTION INPUT ;
    PORT
      LAYER met2 ;
        RECT 2238.450 0.000 2238.730 4.000 ;
    END
  END wbs_adr_i[8]
  PIN wbs_adr_i[9]
    DIRECTION INPUT ;
    PORT
      LAYER met2 ;
        RECT 181.330 3696.000 181.610 3700.000 ;
    END
  END wbs_adr_i[9]
  PIN wbs_cyc_i
    DIRECTION INPUT ;
    PORT
      LAYER met2 ;
        RECT 1340.530 0.000 1340.810 4.000 ;
    END
  END wbs_cyc_i
  PIN wbs_dat_i[0]
    DIRECTION INPUT ;
    PORT
      LAYER met3 ;
        RECT 0.000 1856.440 4.000 1857.040 ;
    END
  END wbs_dat_i[0]
  PIN wbs_dat_i[10]
    DIRECTION INPUT ;
    PORT
      LAYER met2 ;
        RECT 2485.010 3696.000 2485.290 3700.000 ;
    END
  END wbs_dat_i[10]
  PIN wbs_dat_i[11]
    DIRECTION INPUT ;
    PORT
      LAYER met3 ;
        RECT 0.000 228.520 4.000 229.120 ;
    END
  END wbs_dat_i[11]
  PIN wbs_dat_i[12]
    DIRECTION INPUT ;
    PORT
      LAYER met2 ;
        RECT 2468.450 3696.000 2468.730 3700.000 ;
    END
  END wbs_dat_i[12]
  PIN wbs_dat_i[13]
    DIRECTION INPUT ;
    PORT
      LAYER met3 ;
        RECT 2696.000 3608.120 2700.000 3608.720 ;
    END
  END wbs_dat_i[13]
  PIN wbs_dat_i[14]
    DIRECTION INPUT ;
    PORT
      LAYER met2 ;
        RECT 2129.890 3696.000 2130.170 3700.000 ;
    END
  END wbs_dat_i[14]
  PIN wbs_dat_i[15]
    DIRECTION INPUT ;
    PORT
      LAYER met2 ;
        RECT 1086.610 0.000 1086.890 4.000 ;
    END
  END wbs_dat_i[15]
  PIN wbs_dat_i[16]
    DIRECTION INPUT ;
    PORT
      LAYER met2 ;
        RECT 113.250 3696.000 113.530 3700.000 ;
    END
  END wbs_dat_i[16]
  PIN wbs_dat_i[17]
    DIRECTION INPUT ;
    PORT
      LAYER met3 ;
        RECT 0.000 2707.800 4.000 2708.400 ;
    END
  END wbs_dat_i[17]
  PIN wbs_dat_i[18]
    DIRECTION INPUT ;
    PORT
      LAYER met2 ;
        RECT 1417.810 3696.000 1418.090 3700.000 ;
    END
  END wbs_dat_i[18]
  PIN wbs_dat_i[19]
    DIRECTION INPUT ;
    PORT
      LAYER met3 ;
        RECT 2696.000 2431.720 2700.000 2432.320 ;
    END
  END wbs_dat_i[19]
  PIN wbs_dat_i[1]
    DIRECTION INPUT ;
    PORT
      LAYER met3 ;
        RECT 2696.000 2480.680 2700.000 2481.280 ;
    END
  END wbs_dat_i[1]
  PIN wbs_dat_i[20]
    DIRECTION INPUT ;
    PORT
      LAYER met2 ;
        RECT 28.610 3696.000 28.890 3700.000 ;
    END
  END wbs_dat_i[20]
  PIN wbs_dat_i[21]
    DIRECTION INPUT ;
    PORT
      LAYER met2 ;
        RECT 899.850 0.000 900.130 4.000 ;
    END
  END wbs_dat_i[21]
  PIN wbs_dat_i[22]
    DIRECTION INPUT ;
    PORT
      LAYER met3 ;
        RECT 2696.000 753.480 2700.000 754.080 ;
    END
  END wbs_dat_i[22]
  PIN wbs_dat_i[23]
    DIRECTION INPUT ;
    PORT
      LAYER met3 ;
        RECT 2696.000 878.600 2700.000 879.200 ;
    END
  END wbs_dat_i[23]
  PIN wbs_dat_i[24]
    DIRECTION INPUT ;
    PORT
      LAYER met2 ;
        RECT 2323.090 0.000 2323.370 4.000 ;
    END
  END wbs_dat_i[24]
  PIN wbs_dat_i[25]
    DIRECTION INPUT ;
    PORT
      LAYER met2 ;
        RECT 357.970 0.000 358.250 4.000 ;
    END
  END wbs_dat_i[25]
  PIN wbs_dat_i[26]
    DIRECTION INPUT ;
    PORT
      LAYER met3 ;
        RECT 2696.000 2155.640 2700.000 2156.240 ;
    END
  END wbs_dat_i[26]
  PIN wbs_dat_i[27]
    DIRECTION INPUT ;
    PORT
      LAYER met2 ;
        RECT 1747.170 0.000 1747.450 4.000 ;
    END
  END wbs_dat_i[27]
  PIN wbs_dat_i[28]
    DIRECTION INPUT ;
    PORT
      LAYER met2 ;
        RECT 1221.850 0.000 1222.130 4.000 ;
    END
  END wbs_dat_i[28]
  PIN wbs_dat_i[29]
    DIRECTION INPUT ;
    PORT
      LAYER met2 ;
        RECT 1764.650 0.000 1764.930 4.000 ;
    END
  END wbs_dat_i[29]
  PIN wbs_dat_i[2]
    DIRECTION INPUT ;
    PORT
      LAYER met3 ;
        RECT 0.000 2532.360 4.000 2532.960 ;
    END
  END wbs_dat_i[2]
  PIN wbs_dat_i[30]
    DIRECTION INPUT ;
    PORT
      LAYER met2 ;
        RECT 2543.890 0.000 2544.170 4.000 ;
    END
  END wbs_dat_i[30]
  PIN wbs_dat_i[31]
    DIRECTION INPUT ;
    PORT
      LAYER met2 ;
        RECT 1435.290 3696.000 1435.570 3700.000 ;
    END
  END wbs_dat_i[31]
  PIN wbs_dat_i[3]
    DIRECTION INPUT ;
    PORT
      LAYER met2 ;
        RECT 798.650 0.000 798.930 4.000 ;
    END
  END wbs_dat_i[3]
  PIN wbs_dat_i[4]
    DIRECTION INPUT ;
    PORT
      LAYER met2 ;
        RECT 909.970 3696.000 910.250 3700.000 ;
    END
  END wbs_dat_i[4]
  PIN wbs_dat_i[5]
    DIRECTION INPUT ;
    PORT
      LAYER met2 ;
        RECT 2281.690 3696.000 2281.970 3700.000 ;
    END
  END wbs_dat_i[5]
  PIN wbs_dat_i[6]
    DIRECTION INPUT ;
    PORT
      LAYER met3 ;
        RECT 0.000 2207.320 4.000 2207.920 ;
    END
  END wbs_dat_i[6]
  PIN wbs_dat_i[7]
    DIRECTION INPUT ;
    PORT
      LAYER met2 ;
        RECT 1062.690 3696.000 1062.970 3700.000 ;
    END
  END wbs_dat_i[7]
  PIN wbs_dat_i[8]
    DIRECTION INPUT ;
    PORT
      LAYER met2 ;
        RECT 2628.530 0.000 2628.810 4.000 ;
    END
  END wbs_dat_i[8]
  PIN wbs_dat_i[9]
    DIRECTION INPUT ;
    PORT
      LAYER met3 ;
        RECT 0.000 1806.120 4.000 1806.720 ;
    END
  END wbs_dat_i[9]
  PIN wbs_dat_o[0]
    DIRECTION OUTPUT TRISTATE ;
    PORT
      LAYER met3 ;
        RECT 2696.000 253.000 2700.000 253.600 ;
    END
  END wbs_dat_o[0]
  PIN wbs_dat_o[10]
    DIRECTION OUTPUT TRISTATE ;
    PORT
      LAYER met2 ;
        RECT 1493.250 0.000 1493.530 4.000 ;
    END
  END wbs_dat_o[10]
  PIN wbs_dat_o[11]
    DIRECTION OUTPUT TRISTATE ;
    PORT
      LAYER met3 ;
        RECT 0.000 1156.040 4.000 1156.640 ;
    END
  END wbs_dat_o[11]
  PIN wbs_dat_o[12]
    DIRECTION OUTPUT TRISTATE ;
    PORT
      LAYER met2 ;
        RECT 46.090 3696.000 46.370 3700.000 ;
    END
  END wbs_dat_o[12]
  PIN wbs_dat_o[13]
    DIRECTION OUTPUT TRISTATE ;
    PORT
      LAYER met2 ;
        RECT 2688.330 3696.000 2688.610 3700.000 ;
    END
  END wbs_dat_o[13]
  PIN wbs_dat_o[14]
    DIRECTION OUTPUT TRISTATE ;
    PORT
      LAYER met2 ;
        RECT 1662.530 0.000 1662.810 4.000 ;
    END
  END wbs_dat_o[14]
  PIN wbs_dat_o[15]
    DIRECTION OUTPUT TRISTATE ;
    PORT
      LAYER met2 ;
        RECT 307.370 0.000 307.650 4.000 ;
    END
  END wbs_dat_o[15]
  PIN wbs_dat_o[16]
    DIRECTION OUTPUT TRISTATE ;
    PORT
      LAYER met2 ;
        RECT 2333.210 3696.000 2333.490 3700.000 ;
    END
  END wbs_dat_o[16]
  PIN wbs_dat_o[17]
    DIRECTION OUTPUT TRISTATE ;
    PORT
      LAYER met2 ;
        RECT 418.690 3696.000 418.970 3700.000 ;
    END
  END wbs_dat_o[17]
  PIN wbs_dat_o[18]
    DIRECTION OUTPUT TRISTATE ;
    PORT
      LAYER met2 ;
        RECT 807.850 3696.000 808.130 3700.000 ;
    END
  END wbs_dat_o[18]
  PIN wbs_dat_o[19]
    DIRECTION OUTPUT TRISTATE ;
    PORT
      LAYER met2 ;
        RECT 392.010 0.000 392.290 4.000 ;
    END
  END wbs_dat_o[19]
  PIN wbs_dat_o[1]
    DIRECTION OUTPUT TRISTATE ;
    PORT
      LAYER met3 ;
        RECT 0.000 153.720 4.000 154.320 ;
    END
  END wbs_dat_o[1]
  PIN wbs_dat_o[20]
    DIRECTION OUTPUT TRISTATE ;
    PORT
      LAYER met2 ;
        RECT 815.210 0.000 815.490 4.000 ;
    END
  END wbs_dat_o[20]
  PIN wbs_dat_o[21]
    DIRECTION OUTPUT TRISTATE ;
    PORT
      LAYER met2 ;
        RECT 1950.490 0.000 1950.770 4.000 ;
    END
  END wbs_dat_o[21]
  PIN wbs_dat_o[22]
    DIRECTION OUTPUT TRISTATE ;
    PORT
      LAYER met2 ;
        RECT 2221.890 0.000 2222.170 4.000 ;
    END
  END wbs_dat_o[22]
  PIN wbs_dat_o[23]
    DIRECTION OUTPUT TRISTATE ;
    PORT
      LAYER met3 ;
        RECT 0.000 2433.080 4.000 2433.680 ;
    END
  END wbs_dat_o[23]
  PIN wbs_dat_o[24]
    DIRECTION OUTPUT TRISTATE ;
    PORT
      LAYER met2 ;
        RECT 638.570 3696.000 638.850 3700.000 ;
    END
  END wbs_dat_o[24]
  PIN wbs_dat_o[25]
    DIRECTION OUTPUT TRISTATE ;
    PORT
      LAYER met3 ;
        RECT 0.000 129.240 4.000 129.840 ;
    END
  END wbs_dat_o[25]
  PIN wbs_dat_o[26]
    DIRECTION OUTPUT TRISTATE ;
    PORT
      LAYER met3 ;
        RECT 0.000 2507.880 4.000 2508.480 ;
    END
  END wbs_dat_o[26]
  PIN wbs_dat_o[27]
    DIRECTION OUTPUT TRISTATE ;
    PORT
      LAYER met3 ;
        RECT 2696.000 3107.640 2700.000 3108.240 ;
    END
  END wbs_dat_o[27]
  PIN wbs_dat_o[28]
    DIRECTION OUTPUT TRISTATE ;
    PORT
      LAYER met2 ;
        RECT 875.930 3696.000 876.210 3700.000 ;
    END
  END wbs_dat_o[28]
  PIN wbs_dat_o[29]
    DIRECTION OUTPUT TRISTATE ;
    PORT
      LAYER met2 ;
        RECT 70.010 0.000 70.290 4.000 ;
    END
  END wbs_dat_o[29]
  PIN wbs_dat_o[2]
    DIRECTION OUTPUT TRISTATE ;
    PORT
      LAYER met3 ;
        RECT 0.000 904.440 4.000 905.040 ;
    END
  END wbs_dat_o[2]
  PIN wbs_dat_o[30]
    DIRECTION OUTPUT TRISTATE ;
    PORT
      LAYER met3 ;
        RECT 0.000 3635.320 4.000 3635.920 ;
    END
  END wbs_dat_o[30]
  PIN wbs_dat_o[31]
    DIRECTION OUTPUT TRISTATE ;
    PORT
      LAYER met2 ;
        RECT 689.170 3696.000 689.450 3700.000 ;
    END
  END wbs_dat_o[31]
  PIN wbs_dat_o[3]
    DIRECTION OUTPUT TRISTATE ;
    PORT
      LAYER met2 ;
        RECT 2078.370 3696.000 2078.650 3700.000 ;
    END
  END wbs_dat_o[3]
  PIN wbs_dat_o[4]
    DIRECTION OUTPUT TRISTATE ;
    PORT
      LAYER met2 ;
        RECT 1671.730 3696.000 1672.010 3700.000 ;
    END
  END wbs_dat_o[4]
  PIN wbs_dat_o[5]
    DIRECTION OUTPUT TRISTATE ;
    PORT
      LAYER met2 ;
        RECT 300.010 3696.000 300.290 3700.000 ;
    END
  END wbs_dat_o[5]
  PIN wbs_dat_o[6]
    DIRECTION OUTPUT TRISTATE ;
    PORT
      LAYER met2 ;
        RECT 1781.210 0.000 1781.490 4.000 ;
    END
  END wbs_dat_o[6]
  PIN wbs_dat_o[7]
    DIRECTION OUTPUT TRISTATE ;
    PORT
      LAYER met2 ;
        RECT 1611.930 0.000 1612.210 4.000 ;
    END
  END wbs_dat_o[7]
  PIN wbs_dat_o[8]
    DIRECTION OUTPUT TRISTATE ;
    PORT
      LAYER met3 ;
        RECT 0.000 3234.120 4.000 3234.720 ;
    END
  END wbs_dat_o[8]
  PIN wbs_dat_o[9]
    DIRECTION OUTPUT TRISTATE ;
    PORT
      LAYER met3 ;
        RECT 0.000 2257.640 4.000 2258.240 ;
    END
  END wbs_dat_o[9]
  PIN wbs_sel_i[0]
    DIRECTION INPUT ;
    PORT
      LAYER met3 ;
        RECT 2696.000 1955.720 2700.000 1956.320 ;
    END
  END wbs_sel_i[0]
  PIN wbs_sel_i[1]
    DIRECTION INPUT ;
    PORT
      LAYER met2 ;
        RECT 527.250 0.000 527.530 4.000 ;
    END
  END wbs_sel_i[1]
  PIN wbs_sel_i[2]
    DIRECTION INPUT ;
    PORT
      LAYER met2 ;
        RECT 1350.650 3696.000 1350.930 3700.000 ;
    END
  END wbs_sel_i[2]
  PIN wbs_sel_i[3]
    DIRECTION INPUT ;
    PORT
      LAYER met3 ;
        RECT 2696.000 1780.280 2700.000 1780.880 ;
    END
  END wbs_sel_i[3]
  PIN wbs_stb_i
    DIRECTION INPUT ;
    PORT
      LAYER met3 ;
        RECT 0.000 353.640 4.000 354.240 ;
    END
  END wbs_stb_i
  PIN wbs_we_i
    DIRECTION INPUT ;
    PORT
      LAYER met3 ;
        RECT 0.000 379.480 4.000 380.080 ;
    END
  END wbs_we_i
  OBS
      LAYER li1 ;
        RECT 45.685 16.745 2685.795 3695.715 ;
      LAYER met1 ;
        RECT 2.830 4.460 2695.990 3695.760 ;
      LAYER met2 ;
        RECT 2.860 3695.720 11.770 3696.000 ;
        RECT 12.610 3695.720 28.330 3696.000 ;
        RECT 29.170 3695.720 45.810 3696.000 ;
        RECT 46.650 3695.720 62.370 3696.000 ;
        RECT 63.210 3695.720 78.930 3696.000 ;
        RECT 79.770 3695.720 96.410 3696.000 ;
        RECT 97.250 3695.720 112.970 3696.000 ;
        RECT 113.810 3695.720 130.450 3696.000 ;
        RECT 131.290 3695.720 147.010 3696.000 ;
        RECT 147.850 3695.720 164.490 3696.000 ;
        RECT 165.330 3695.720 181.050 3696.000 ;
        RECT 181.890 3695.720 197.610 3696.000 ;
        RECT 198.450 3695.720 215.090 3696.000 ;
        RECT 215.930 3695.720 231.650 3696.000 ;
        RECT 232.490 3695.720 249.130 3696.000 ;
        RECT 249.970 3695.720 265.690 3696.000 ;
        RECT 266.530 3695.720 282.250 3696.000 ;
        RECT 283.090 3695.720 299.730 3696.000 ;
        RECT 300.570 3695.720 316.290 3696.000 ;
        RECT 317.130 3695.720 333.770 3696.000 ;
        RECT 334.610 3695.720 350.330 3696.000 ;
        RECT 351.170 3695.720 367.810 3696.000 ;
        RECT 368.650 3695.720 384.370 3696.000 ;
        RECT 385.210 3695.720 400.930 3696.000 ;
        RECT 401.770 3695.720 418.410 3696.000 ;
        RECT 419.250 3695.720 434.970 3696.000 ;
        RECT 435.810 3695.720 452.450 3696.000 ;
        RECT 453.290 3695.720 469.010 3696.000 ;
        RECT 469.850 3695.720 485.570 3696.000 ;
        RECT 486.410 3695.720 503.050 3696.000 ;
        RECT 503.890 3695.720 519.610 3696.000 ;
        RECT 520.450 3695.720 537.090 3696.000 ;
        RECT 537.930 3695.720 553.650 3696.000 ;
        RECT 554.490 3695.720 570.210 3696.000 ;
        RECT 571.050 3695.720 587.690 3696.000 ;
        RECT 588.530 3695.720 604.250 3696.000 ;
        RECT 605.090 3695.720 621.730 3696.000 ;
        RECT 622.570 3695.720 638.290 3696.000 ;
        RECT 639.130 3695.720 655.770 3696.000 ;
        RECT 656.610 3695.720 672.330 3696.000 ;
        RECT 673.170 3695.720 688.890 3696.000 ;
        RECT 689.730 3695.720 706.370 3696.000 ;
        RECT 707.210 3695.720 722.930 3696.000 ;
        RECT 723.770 3695.720 740.410 3696.000 ;
        RECT 741.250 3695.720 756.970 3696.000 ;
        RECT 757.810 3695.720 773.530 3696.000 ;
        RECT 774.370 3695.720 791.010 3696.000 ;
        RECT 791.850 3695.720 807.570 3696.000 ;
        RECT 808.410 3695.720 825.050 3696.000 ;
        RECT 825.890 3695.720 841.610 3696.000 ;
        RECT 842.450 3695.720 859.090 3696.000 ;
        RECT 859.930 3695.720 875.650 3696.000 ;
        RECT 876.490 3695.720 892.210 3696.000 ;
        RECT 893.050 3695.720 909.690 3696.000 ;
        RECT 910.530 3695.720 926.250 3696.000 ;
        RECT 927.090 3695.720 943.730 3696.000 ;
        RECT 944.570 3695.720 960.290 3696.000 ;
        RECT 961.130 3695.720 976.850 3696.000 ;
        RECT 977.690 3695.720 994.330 3696.000 ;
        RECT 995.170 3695.720 1010.890 3696.000 ;
        RECT 1011.730 3695.720 1028.370 3696.000 ;
        RECT 1029.210 3695.720 1044.930 3696.000 ;
        RECT 1045.770 3695.720 1062.410 3696.000 ;
        RECT 1063.250 3695.720 1078.970 3696.000 ;
        RECT 1079.810 3695.720 1095.530 3696.000 ;
        RECT 1096.370 3695.720 1113.010 3696.000 ;
        RECT 1113.850 3695.720 1129.570 3696.000 ;
        RECT 1130.410 3695.720 1147.050 3696.000 ;
        RECT 1147.890 3695.720 1163.610 3696.000 ;
        RECT 1164.450 3695.720 1180.170 3696.000 ;
        RECT 1181.010 3695.720 1197.650 3696.000 ;
        RECT 1198.490 3695.720 1214.210 3696.000 ;
        RECT 1215.050 3695.720 1231.690 3696.000 ;
        RECT 1232.530 3695.720 1248.250 3696.000 ;
        RECT 1249.090 3695.720 1264.810 3696.000 ;
        RECT 1265.650 3695.720 1282.290 3696.000 ;
        RECT 1283.130 3695.720 1298.850 3696.000 ;
        RECT 1299.690 3695.720 1316.330 3696.000 ;
        RECT 1317.170 3695.720 1332.890 3696.000 ;
        RECT 1333.730 3695.720 1350.370 3696.000 ;
        RECT 1351.210 3695.720 1366.930 3696.000 ;
        RECT 1367.770 3695.720 1383.490 3696.000 ;
        RECT 1384.330 3695.720 1400.970 3696.000 ;
        RECT 1401.810 3695.720 1417.530 3696.000 ;
        RECT 1418.370 3695.720 1435.010 3696.000 ;
        RECT 1435.850 3695.720 1451.570 3696.000 ;
        RECT 1452.410 3695.720 1468.130 3696.000 ;
        RECT 1468.970 3695.720 1485.610 3696.000 ;
        RECT 1486.450 3695.720 1502.170 3696.000 ;
        RECT 1503.010 3695.720 1519.650 3696.000 ;
        RECT 1520.490 3695.720 1536.210 3696.000 ;
        RECT 1537.050 3695.720 1553.690 3696.000 ;
        RECT 1554.530 3695.720 1570.250 3696.000 ;
        RECT 1571.090 3695.720 1586.810 3696.000 ;
        RECT 1587.650 3695.720 1604.290 3696.000 ;
        RECT 1605.130 3695.720 1620.850 3696.000 ;
        RECT 1621.690 3695.720 1638.330 3696.000 ;
        RECT 1639.170 3695.720 1654.890 3696.000 ;
        RECT 1655.730 3695.720 1671.450 3696.000 ;
        RECT 1672.290 3695.720 1688.930 3696.000 ;
        RECT 1689.770 3695.720 1705.490 3696.000 ;
        RECT 1706.330 3695.720 1722.970 3696.000 ;
        RECT 1723.810 3695.720 1739.530 3696.000 ;
        RECT 1740.370 3695.720 1757.010 3696.000 ;
        RECT 1757.850 3695.720 1773.570 3696.000 ;
        RECT 1774.410 3695.720 1790.130 3696.000 ;
        RECT 1790.970 3695.720 1807.610 3696.000 ;
        RECT 1808.450 3695.720 1824.170 3696.000 ;
        RECT 1825.010 3695.720 1841.650 3696.000 ;
        RECT 1842.490 3695.720 1858.210 3696.000 ;
        RECT 1859.050 3695.720 1874.770 3696.000 ;
        RECT 1875.610 3695.720 1892.250 3696.000 ;
        RECT 1893.090 3695.720 1908.810 3696.000 ;
        RECT 1909.650 3695.720 1926.290 3696.000 ;
        RECT 1927.130 3695.720 1942.850 3696.000 ;
        RECT 1943.690 3695.720 1959.410 3696.000 ;
        RECT 1960.250 3695.720 1976.890 3696.000 ;
        RECT 1977.730 3695.720 1993.450 3696.000 ;
        RECT 1994.290 3695.720 2010.930 3696.000 ;
        RECT 2011.770 3695.720 2027.490 3696.000 ;
        RECT 2028.330 3695.720 2044.970 3696.000 ;
        RECT 2045.810 3695.720 2061.530 3696.000 ;
        RECT 2062.370 3695.720 2078.090 3696.000 ;
        RECT 2078.930 3695.720 2095.570 3696.000 ;
        RECT 2096.410 3695.720 2112.130 3696.000 ;
        RECT 2112.970 3695.720 2129.610 3696.000 ;
        RECT 2130.450 3695.720 2146.170 3696.000 ;
        RECT 2147.010 3695.720 2162.730 3696.000 ;
        RECT 2163.570 3695.720 2180.210 3696.000 ;
        RECT 2181.050 3695.720 2196.770 3696.000 ;
        RECT 2197.610 3695.720 2214.250 3696.000 ;
        RECT 2215.090 3695.720 2230.810 3696.000 ;
        RECT 2231.650 3695.720 2248.290 3696.000 ;
        RECT 2249.130 3695.720 2264.850 3696.000 ;
        RECT 2265.690 3695.720 2281.410 3696.000 ;
        RECT 2282.250 3695.720 2298.890 3696.000 ;
        RECT 2299.730 3695.720 2315.450 3696.000 ;
        RECT 2316.290 3695.720 2332.930 3696.000 ;
        RECT 2333.770 3695.720 2349.490 3696.000 ;
        RECT 2350.330 3695.720 2366.050 3696.000 ;
        RECT 2366.890 3695.720 2383.530 3696.000 ;
        RECT 2384.370 3695.720 2400.090 3696.000 ;
        RECT 2400.930 3695.720 2417.570 3696.000 ;
        RECT 2418.410 3695.720 2434.130 3696.000 ;
        RECT 2434.970 3695.720 2450.690 3696.000 ;
        RECT 2451.530 3695.720 2468.170 3696.000 ;
        RECT 2469.010 3695.720 2484.730 3696.000 ;
        RECT 2485.570 3695.720 2502.210 3696.000 ;
        RECT 2503.050 3695.720 2518.770 3696.000 ;
        RECT 2519.610 3695.720 2536.250 3696.000 ;
        RECT 2537.090 3695.720 2552.810 3696.000 ;
        RECT 2553.650 3695.720 2569.370 3696.000 ;
        RECT 2570.210 3695.720 2586.850 3696.000 ;
        RECT 2587.690 3695.720 2603.410 3696.000 ;
        RECT 2604.250 3695.720 2620.890 3696.000 ;
        RECT 2621.730 3695.720 2637.450 3696.000 ;
        RECT 2638.290 3695.720 2654.010 3696.000 ;
        RECT 2654.850 3695.720 2671.490 3696.000 ;
        RECT 2672.330 3695.720 2688.050 3696.000 ;
        RECT 2688.890 3695.720 2695.960 3696.000 ;
        RECT 2.860 4.280 2695.960 3695.720 ;
        RECT 3.410 4.000 19.130 4.280 ;
        RECT 19.970 4.000 35.690 4.280 ;
        RECT 36.530 4.000 53.170 4.280 ;
        RECT 54.010 4.000 69.730 4.280 ;
        RECT 70.570 4.000 87.210 4.280 ;
        RECT 88.050 4.000 103.770 4.280 ;
        RECT 104.610 4.000 120.330 4.280 ;
        RECT 121.170 4.000 137.810 4.280 ;
        RECT 138.650 4.000 154.370 4.280 ;
        RECT 155.210 4.000 171.850 4.280 ;
        RECT 172.690 4.000 188.410 4.280 ;
        RECT 189.250 4.000 204.970 4.280 ;
        RECT 205.810 4.000 222.450 4.280 ;
        RECT 223.290 4.000 239.010 4.280 ;
        RECT 239.850 4.000 256.490 4.280 ;
        RECT 257.330 4.000 273.050 4.280 ;
        RECT 273.890 4.000 290.530 4.280 ;
        RECT 291.370 4.000 307.090 4.280 ;
        RECT 307.930 4.000 323.650 4.280 ;
        RECT 324.490 4.000 341.130 4.280 ;
        RECT 341.970 4.000 357.690 4.280 ;
        RECT 358.530 4.000 375.170 4.280 ;
        RECT 376.010 4.000 391.730 4.280 ;
        RECT 392.570 4.000 408.290 4.280 ;
        RECT 409.130 4.000 425.770 4.280 ;
        RECT 426.610 4.000 442.330 4.280 ;
        RECT 443.170 4.000 459.810 4.280 ;
        RECT 460.650 4.000 476.370 4.280 ;
        RECT 477.210 4.000 493.850 4.280 ;
        RECT 494.690 4.000 510.410 4.280 ;
        RECT 511.250 4.000 526.970 4.280 ;
        RECT 527.810 4.000 544.450 4.280 ;
        RECT 545.290 4.000 561.010 4.280 ;
        RECT 561.850 4.000 578.490 4.280 ;
        RECT 579.330 4.000 595.050 4.280 ;
        RECT 595.890 4.000 611.610 4.280 ;
        RECT 612.450 4.000 629.090 4.280 ;
        RECT 629.930 4.000 645.650 4.280 ;
        RECT 646.490 4.000 663.130 4.280 ;
        RECT 663.970 4.000 679.690 4.280 ;
        RECT 680.530 4.000 696.250 4.280 ;
        RECT 697.090 4.000 713.730 4.280 ;
        RECT 714.570 4.000 730.290 4.280 ;
        RECT 731.130 4.000 747.770 4.280 ;
        RECT 748.610 4.000 764.330 4.280 ;
        RECT 765.170 4.000 781.810 4.280 ;
        RECT 782.650 4.000 798.370 4.280 ;
        RECT 799.210 4.000 814.930 4.280 ;
        RECT 815.770 4.000 832.410 4.280 ;
        RECT 833.250 4.000 848.970 4.280 ;
        RECT 849.810 4.000 866.450 4.280 ;
        RECT 867.290 4.000 883.010 4.280 ;
        RECT 883.850 4.000 899.570 4.280 ;
        RECT 900.410 4.000 917.050 4.280 ;
        RECT 917.890 4.000 933.610 4.280 ;
        RECT 934.450 4.000 951.090 4.280 ;
        RECT 951.930 4.000 967.650 4.280 ;
        RECT 968.490 4.000 985.130 4.280 ;
        RECT 985.970 4.000 1001.690 4.280 ;
        RECT 1002.530 4.000 1018.250 4.280 ;
        RECT 1019.090 4.000 1035.730 4.280 ;
        RECT 1036.570 4.000 1052.290 4.280 ;
        RECT 1053.130 4.000 1069.770 4.280 ;
        RECT 1070.610 4.000 1086.330 4.280 ;
        RECT 1087.170 4.000 1102.890 4.280 ;
        RECT 1103.730 4.000 1120.370 4.280 ;
        RECT 1121.210 4.000 1136.930 4.280 ;
        RECT 1137.770 4.000 1154.410 4.280 ;
        RECT 1155.250 4.000 1170.970 4.280 ;
        RECT 1171.810 4.000 1188.450 4.280 ;
        RECT 1189.290 4.000 1205.010 4.280 ;
        RECT 1205.850 4.000 1221.570 4.280 ;
        RECT 1222.410 4.000 1239.050 4.280 ;
        RECT 1239.890 4.000 1255.610 4.280 ;
        RECT 1256.450 4.000 1273.090 4.280 ;
        RECT 1273.930 4.000 1289.650 4.280 ;
        RECT 1290.490 4.000 1306.210 4.280 ;
        RECT 1307.050 4.000 1323.690 4.280 ;
        RECT 1324.530 4.000 1340.250 4.280 ;
        RECT 1341.090 4.000 1357.730 4.280 ;
        RECT 1358.570 4.000 1374.290 4.280 ;
        RECT 1375.130 4.000 1390.850 4.280 ;
        RECT 1391.690 4.000 1408.330 4.280 ;
        RECT 1409.170 4.000 1424.890 4.280 ;
        RECT 1425.730 4.000 1442.370 4.280 ;
        RECT 1443.210 4.000 1458.930 4.280 ;
        RECT 1459.770 4.000 1476.410 4.280 ;
        RECT 1477.250 4.000 1492.970 4.280 ;
        RECT 1493.810 4.000 1509.530 4.280 ;
        RECT 1510.370 4.000 1527.010 4.280 ;
        RECT 1527.850 4.000 1543.570 4.280 ;
        RECT 1544.410 4.000 1561.050 4.280 ;
        RECT 1561.890 4.000 1577.610 4.280 ;
        RECT 1578.450 4.000 1594.170 4.280 ;
        RECT 1595.010 4.000 1611.650 4.280 ;
        RECT 1612.490 4.000 1628.210 4.280 ;
        RECT 1629.050 4.000 1645.690 4.280 ;
        RECT 1646.530 4.000 1662.250 4.280 ;
        RECT 1663.090 4.000 1679.730 4.280 ;
        RECT 1680.570 4.000 1696.290 4.280 ;
        RECT 1697.130 4.000 1712.850 4.280 ;
        RECT 1713.690 4.000 1730.330 4.280 ;
        RECT 1731.170 4.000 1746.890 4.280 ;
        RECT 1747.730 4.000 1764.370 4.280 ;
        RECT 1765.210 4.000 1780.930 4.280 ;
        RECT 1781.770 4.000 1797.490 4.280 ;
        RECT 1798.330 4.000 1814.970 4.280 ;
        RECT 1815.810 4.000 1831.530 4.280 ;
        RECT 1832.370 4.000 1849.010 4.280 ;
        RECT 1849.850 4.000 1865.570 4.280 ;
        RECT 1866.410 4.000 1882.130 4.280 ;
        RECT 1882.970 4.000 1899.610 4.280 ;
        RECT 1900.450 4.000 1916.170 4.280 ;
        RECT 1917.010 4.000 1933.650 4.280 ;
        RECT 1934.490 4.000 1950.210 4.280 ;
        RECT 1951.050 4.000 1967.690 4.280 ;
        RECT 1968.530 4.000 1984.250 4.280 ;
        RECT 1985.090 4.000 2000.810 4.280 ;
        RECT 2001.650 4.000 2018.290 4.280 ;
        RECT 2019.130 4.000 2034.850 4.280 ;
        RECT 2035.690 4.000 2052.330 4.280 ;
        RECT 2053.170 4.000 2068.890 4.280 ;
        RECT 2069.730 4.000 2085.450 4.280 ;
        RECT 2086.290 4.000 2102.930 4.280 ;
        RECT 2103.770 4.000 2119.490 4.280 ;
        RECT 2120.330 4.000 2136.970 4.280 ;
        RECT 2137.810 4.000 2153.530 4.280 ;
        RECT 2154.370 4.000 2171.010 4.280 ;
        RECT 2171.850 4.000 2187.570 4.280 ;
        RECT 2188.410 4.000 2204.130 4.280 ;
        RECT 2204.970 4.000 2221.610 4.280 ;
        RECT 2222.450 4.000 2238.170 4.280 ;
        RECT 2239.010 4.000 2255.650 4.280 ;
        RECT 2256.490 4.000 2272.210 4.280 ;
        RECT 2273.050 4.000 2288.770 4.280 ;
        RECT 2289.610 4.000 2306.250 4.280 ;
        RECT 2307.090 4.000 2322.810 4.280 ;
        RECT 2323.650 4.000 2340.290 4.280 ;
        RECT 2341.130 4.000 2356.850 4.280 ;
        RECT 2357.690 4.000 2374.330 4.280 ;
        RECT 2375.170 4.000 2390.890 4.280 ;
        RECT 2391.730 4.000 2407.450 4.280 ;
        RECT 2408.290 4.000 2424.930 4.280 ;
        RECT 2425.770 4.000 2441.490 4.280 ;
        RECT 2442.330 4.000 2458.970 4.280 ;
        RECT 2459.810 4.000 2475.530 4.280 ;
        RECT 2476.370 4.000 2492.090 4.280 ;
        RECT 2492.930 4.000 2509.570 4.280 ;
        RECT 2510.410 4.000 2526.130 4.280 ;
        RECT 2526.970 4.000 2543.610 4.280 ;
        RECT 2544.450 4.000 2560.170 4.280 ;
        RECT 2561.010 4.000 2576.730 4.280 ;
        RECT 2577.570 4.000 2594.210 4.280 ;
        RECT 2595.050 4.000 2610.770 4.280 ;
        RECT 2611.610 4.000 2628.250 4.280 ;
        RECT 2629.090 4.000 2644.810 4.280 ;
        RECT 2645.650 4.000 2662.290 4.280 ;
        RECT 2663.130 4.000 2678.850 4.280 ;
        RECT 2679.690 4.000 2695.410 4.280 ;
      LAYER met3 ;
        RECT 4.400 3683.920 2696.000 3684.745 ;
        RECT 4.400 3683.880 2695.600 3683.920 ;
        RECT 4.000 3682.520 2695.600 3683.880 ;
        RECT 4.000 3660.800 2696.000 3682.520 ;
        RECT 4.400 3659.440 2696.000 3660.800 ;
        RECT 4.400 3659.400 2695.600 3659.440 ;
        RECT 4.000 3658.040 2695.600 3659.400 ;
        RECT 4.000 3636.320 2696.000 3658.040 ;
        RECT 4.400 3634.920 2696.000 3636.320 ;
        RECT 4.000 3633.600 2696.000 3634.920 ;
        RECT 4.000 3632.200 2695.600 3633.600 ;
        RECT 4.000 3610.480 2696.000 3632.200 ;
        RECT 4.400 3609.120 2696.000 3610.480 ;
        RECT 4.400 3609.080 2695.600 3609.120 ;
        RECT 4.000 3607.720 2695.600 3609.080 ;
        RECT 4.000 3586.000 2696.000 3607.720 ;
        RECT 4.400 3584.640 2696.000 3586.000 ;
        RECT 4.400 3584.600 2695.600 3584.640 ;
        RECT 4.000 3583.240 2695.600 3584.600 ;
        RECT 4.000 3560.160 2696.000 3583.240 ;
        RECT 4.400 3558.800 2696.000 3560.160 ;
        RECT 4.400 3558.760 2695.600 3558.800 ;
        RECT 4.000 3557.400 2695.600 3558.760 ;
        RECT 4.000 3535.680 2696.000 3557.400 ;
        RECT 4.400 3534.320 2696.000 3535.680 ;
        RECT 4.400 3534.280 2695.600 3534.320 ;
        RECT 4.000 3532.920 2695.600 3534.280 ;
        RECT 4.000 3511.200 2696.000 3532.920 ;
        RECT 4.400 3509.800 2696.000 3511.200 ;
        RECT 4.000 3508.480 2696.000 3509.800 ;
        RECT 4.000 3507.080 2695.600 3508.480 ;
        RECT 4.000 3485.360 2696.000 3507.080 ;
        RECT 4.400 3484.000 2696.000 3485.360 ;
        RECT 4.400 3483.960 2695.600 3484.000 ;
        RECT 4.000 3482.600 2695.600 3483.960 ;
        RECT 4.000 3460.880 2696.000 3482.600 ;
        RECT 4.400 3459.520 2696.000 3460.880 ;
        RECT 4.400 3459.480 2695.600 3459.520 ;
        RECT 4.000 3458.120 2695.600 3459.480 ;
        RECT 4.000 3435.040 2696.000 3458.120 ;
        RECT 4.400 3433.680 2696.000 3435.040 ;
        RECT 4.400 3433.640 2695.600 3433.680 ;
        RECT 4.000 3432.280 2695.600 3433.640 ;
        RECT 4.000 3410.560 2696.000 3432.280 ;
        RECT 4.400 3409.200 2696.000 3410.560 ;
        RECT 4.400 3409.160 2695.600 3409.200 ;
        RECT 4.000 3407.800 2695.600 3409.160 ;
        RECT 4.000 3384.720 2696.000 3407.800 ;
        RECT 4.400 3383.360 2696.000 3384.720 ;
        RECT 4.400 3383.320 2695.600 3383.360 ;
        RECT 4.000 3381.960 2695.600 3383.320 ;
        RECT 4.000 3360.240 2696.000 3381.960 ;
        RECT 4.400 3358.880 2696.000 3360.240 ;
        RECT 4.400 3358.840 2695.600 3358.880 ;
        RECT 4.000 3357.480 2695.600 3358.840 ;
        RECT 4.000 3335.760 2696.000 3357.480 ;
        RECT 4.400 3334.360 2696.000 3335.760 ;
        RECT 4.000 3333.040 2696.000 3334.360 ;
        RECT 4.000 3331.640 2695.600 3333.040 ;
        RECT 4.000 3309.920 2696.000 3331.640 ;
        RECT 4.400 3308.560 2696.000 3309.920 ;
        RECT 4.400 3308.520 2695.600 3308.560 ;
        RECT 4.000 3307.160 2695.600 3308.520 ;
        RECT 4.000 3285.440 2696.000 3307.160 ;
        RECT 4.400 3284.080 2696.000 3285.440 ;
        RECT 4.400 3284.040 2695.600 3284.080 ;
        RECT 4.000 3282.680 2695.600 3284.040 ;
        RECT 4.000 3259.600 2696.000 3282.680 ;
        RECT 4.400 3258.240 2696.000 3259.600 ;
        RECT 4.400 3258.200 2695.600 3258.240 ;
        RECT 4.000 3256.840 2695.600 3258.200 ;
        RECT 4.000 3235.120 2696.000 3256.840 ;
        RECT 4.400 3233.760 2696.000 3235.120 ;
        RECT 4.400 3233.720 2695.600 3233.760 ;
        RECT 4.000 3232.360 2695.600 3233.720 ;
        RECT 4.000 3210.640 2696.000 3232.360 ;
        RECT 4.400 3209.240 2696.000 3210.640 ;
        RECT 4.000 3207.920 2696.000 3209.240 ;
        RECT 4.000 3206.520 2695.600 3207.920 ;
        RECT 4.000 3184.800 2696.000 3206.520 ;
        RECT 4.400 3183.440 2696.000 3184.800 ;
        RECT 4.400 3183.400 2695.600 3183.440 ;
        RECT 4.000 3182.040 2695.600 3183.400 ;
        RECT 4.000 3160.320 2696.000 3182.040 ;
        RECT 4.400 3158.960 2696.000 3160.320 ;
        RECT 4.400 3158.920 2695.600 3158.960 ;
        RECT 4.000 3157.560 2695.600 3158.920 ;
        RECT 4.000 3134.480 2696.000 3157.560 ;
        RECT 4.400 3133.120 2696.000 3134.480 ;
        RECT 4.400 3133.080 2695.600 3133.120 ;
        RECT 4.000 3131.720 2695.600 3133.080 ;
        RECT 4.000 3110.000 2696.000 3131.720 ;
        RECT 4.400 3108.640 2696.000 3110.000 ;
        RECT 4.400 3108.600 2695.600 3108.640 ;
        RECT 4.000 3107.240 2695.600 3108.600 ;
        RECT 4.000 3084.160 2696.000 3107.240 ;
        RECT 4.400 3082.800 2696.000 3084.160 ;
        RECT 4.400 3082.760 2695.600 3082.800 ;
        RECT 4.000 3081.400 2695.600 3082.760 ;
        RECT 4.000 3059.680 2696.000 3081.400 ;
        RECT 4.400 3058.320 2696.000 3059.680 ;
        RECT 4.400 3058.280 2695.600 3058.320 ;
        RECT 4.000 3056.920 2695.600 3058.280 ;
        RECT 4.000 3035.200 2696.000 3056.920 ;
        RECT 4.400 3033.840 2696.000 3035.200 ;
        RECT 4.400 3033.800 2695.600 3033.840 ;
        RECT 4.000 3032.440 2695.600 3033.800 ;
        RECT 4.000 3009.360 2696.000 3032.440 ;
        RECT 4.400 3008.000 2696.000 3009.360 ;
        RECT 4.400 3007.960 2695.600 3008.000 ;
        RECT 4.000 3006.600 2695.600 3007.960 ;
        RECT 4.000 2984.880 2696.000 3006.600 ;
        RECT 4.400 2983.520 2696.000 2984.880 ;
        RECT 4.400 2983.480 2695.600 2983.520 ;
        RECT 4.000 2982.120 2695.600 2983.480 ;
        RECT 4.000 2959.040 2696.000 2982.120 ;
        RECT 4.400 2957.680 2696.000 2959.040 ;
        RECT 4.400 2957.640 2695.600 2957.680 ;
        RECT 4.000 2956.280 2695.600 2957.640 ;
        RECT 4.000 2934.560 2696.000 2956.280 ;
        RECT 4.400 2933.200 2696.000 2934.560 ;
        RECT 4.400 2933.160 2695.600 2933.200 ;
        RECT 4.000 2931.800 2695.600 2933.160 ;
        RECT 4.000 2910.080 2696.000 2931.800 ;
        RECT 4.400 2908.680 2696.000 2910.080 ;
        RECT 4.000 2907.360 2696.000 2908.680 ;
        RECT 4.000 2905.960 2695.600 2907.360 ;
        RECT 4.000 2884.240 2696.000 2905.960 ;
        RECT 4.400 2882.880 2696.000 2884.240 ;
        RECT 4.400 2882.840 2695.600 2882.880 ;
        RECT 4.000 2881.480 2695.600 2882.840 ;
        RECT 4.000 2859.760 2696.000 2881.480 ;
        RECT 4.400 2858.400 2696.000 2859.760 ;
        RECT 4.400 2858.360 2695.600 2858.400 ;
        RECT 4.000 2857.000 2695.600 2858.360 ;
        RECT 4.000 2833.920 2696.000 2857.000 ;
        RECT 4.400 2832.560 2696.000 2833.920 ;
        RECT 4.400 2832.520 2695.600 2832.560 ;
        RECT 4.000 2831.160 2695.600 2832.520 ;
        RECT 4.000 2809.440 2696.000 2831.160 ;
        RECT 4.400 2808.080 2696.000 2809.440 ;
        RECT 4.400 2808.040 2695.600 2808.080 ;
        RECT 4.000 2806.680 2695.600 2808.040 ;
        RECT 4.000 2783.600 2696.000 2806.680 ;
        RECT 4.400 2782.240 2696.000 2783.600 ;
        RECT 4.400 2782.200 2695.600 2782.240 ;
        RECT 4.000 2780.840 2695.600 2782.200 ;
        RECT 4.000 2759.120 2696.000 2780.840 ;
        RECT 4.400 2757.760 2696.000 2759.120 ;
        RECT 4.400 2757.720 2695.600 2757.760 ;
        RECT 4.000 2756.360 2695.600 2757.720 ;
        RECT 4.000 2734.640 2696.000 2756.360 ;
        RECT 4.400 2733.280 2696.000 2734.640 ;
        RECT 4.400 2733.240 2695.600 2733.280 ;
        RECT 4.000 2731.880 2695.600 2733.240 ;
        RECT 4.000 2708.800 2696.000 2731.880 ;
        RECT 4.400 2707.440 2696.000 2708.800 ;
        RECT 4.400 2707.400 2695.600 2707.440 ;
        RECT 4.000 2706.040 2695.600 2707.400 ;
        RECT 4.000 2684.320 2696.000 2706.040 ;
        RECT 4.400 2682.960 2696.000 2684.320 ;
        RECT 4.400 2682.920 2695.600 2682.960 ;
        RECT 4.000 2681.560 2695.600 2682.920 ;
        RECT 4.000 2658.480 2696.000 2681.560 ;
        RECT 4.400 2657.120 2696.000 2658.480 ;
        RECT 4.400 2657.080 2695.600 2657.120 ;
        RECT 4.000 2655.720 2695.600 2657.080 ;
        RECT 4.000 2634.000 2696.000 2655.720 ;
        RECT 4.400 2632.640 2696.000 2634.000 ;
        RECT 4.400 2632.600 2695.600 2632.640 ;
        RECT 4.000 2631.240 2695.600 2632.600 ;
        RECT 4.000 2609.520 2696.000 2631.240 ;
        RECT 4.400 2608.120 2696.000 2609.520 ;
        RECT 4.000 2606.800 2696.000 2608.120 ;
        RECT 4.000 2605.400 2695.600 2606.800 ;
        RECT 4.000 2583.680 2696.000 2605.400 ;
        RECT 4.400 2582.320 2696.000 2583.680 ;
        RECT 4.400 2582.280 2695.600 2582.320 ;
        RECT 4.000 2580.920 2695.600 2582.280 ;
        RECT 4.000 2559.200 2696.000 2580.920 ;
        RECT 4.400 2557.840 2696.000 2559.200 ;
        RECT 4.400 2557.800 2695.600 2557.840 ;
        RECT 4.000 2556.440 2695.600 2557.800 ;
        RECT 4.000 2533.360 2696.000 2556.440 ;
        RECT 4.400 2532.000 2696.000 2533.360 ;
        RECT 4.400 2531.960 2695.600 2532.000 ;
        RECT 4.000 2530.600 2695.600 2531.960 ;
        RECT 4.000 2508.880 2696.000 2530.600 ;
        RECT 4.400 2507.520 2696.000 2508.880 ;
        RECT 4.400 2507.480 2695.600 2507.520 ;
        RECT 4.000 2506.120 2695.600 2507.480 ;
        RECT 4.000 2484.400 2696.000 2506.120 ;
        RECT 4.400 2483.000 2696.000 2484.400 ;
        RECT 4.000 2481.680 2696.000 2483.000 ;
        RECT 4.000 2480.280 2695.600 2481.680 ;
        RECT 4.000 2458.560 2696.000 2480.280 ;
        RECT 4.400 2457.200 2696.000 2458.560 ;
        RECT 4.400 2457.160 2695.600 2457.200 ;
        RECT 4.000 2455.800 2695.600 2457.160 ;
        RECT 4.000 2434.080 2696.000 2455.800 ;
        RECT 4.400 2432.720 2696.000 2434.080 ;
        RECT 4.400 2432.680 2695.600 2432.720 ;
        RECT 4.000 2431.320 2695.600 2432.680 ;
        RECT 4.000 2408.240 2696.000 2431.320 ;
        RECT 4.400 2406.880 2696.000 2408.240 ;
        RECT 4.400 2406.840 2695.600 2406.880 ;
        RECT 4.000 2405.480 2695.600 2406.840 ;
        RECT 4.000 2383.760 2696.000 2405.480 ;
        RECT 4.400 2382.400 2696.000 2383.760 ;
        RECT 4.400 2382.360 2695.600 2382.400 ;
        RECT 4.000 2381.000 2695.600 2382.360 ;
        RECT 4.000 2357.920 2696.000 2381.000 ;
        RECT 4.400 2356.560 2696.000 2357.920 ;
        RECT 4.400 2356.520 2695.600 2356.560 ;
        RECT 4.000 2355.160 2695.600 2356.520 ;
        RECT 4.000 2333.440 2696.000 2355.160 ;
        RECT 4.400 2332.080 2696.000 2333.440 ;
        RECT 4.400 2332.040 2695.600 2332.080 ;
        RECT 4.000 2330.680 2695.600 2332.040 ;
        RECT 4.000 2308.960 2696.000 2330.680 ;
        RECT 4.400 2307.600 2696.000 2308.960 ;
        RECT 4.400 2307.560 2695.600 2307.600 ;
        RECT 4.000 2306.200 2695.600 2307.560 ;
        RECT 4.000 2283.120 2696.000 2306.200 ;
        RECT 4.400 2281.760 2696.000 2283.120 ;
        RECT 4.400 2281.720 2695.600 2281.760 ;
        RECT 4.000 2280.360 2695.600 2281.720 ;
        RECT 4.000 2258.640 2696.000 2280.360 ;
        RECT 4.400 2257.280 2696.000 2258.640 ;
        RECT 4.400 2257.240 2695.600 2257.280 ;
        RECT 4.000 2255.880 2695.600 2257.240 ;
        RECT 4.000 2232.800 2696.000 2255.880 ;
        RECT 4.400 2231.440 2696.000 2232.800 ;
        RECT 4.400 2231.400 2695.600 2231.440 ;
        RECT 4.000 2230.040 2695.600 2231.400 ;
        RECT 4.000 2208.320 2696.000 2230.040 ;
        RECT 4.400 2206.960 2696.000 2208.320 ;
        RECT 4.400 2206.920 2695.600 2206.960 ;
        RECT 4.000 2205.560 2695.600 2206.920 ;
        RECT 4.000 2183.840 2696.000 2205.560 ;
        RECT 4.400 2182.440 2696.000 2183.840 ;
        RECT 4.000 2181.120 2696.000 2182.440 ;
        RECT 4.000 2179.720 2695.600 2181.120 ;
        RECT 4.000 2158.000 2696.000 2179.720 ;
        RECT 4.400 2156.640 2696.000 2158.000 ;
        RECT 4.400 2156.600 2695.600 2156.640 ;
        RECT 4.000 2155.240 2695.600 2156.600 ;
        RECT 4.000 2133.520 2696.000 2155.240 ;
        RECT 4.400 2132.160 2696.000 2133.520 ;
        RECT 4.400 2132.120 2695.600 2132.160 ;
        RECT 4.000 2130.760 2695.600 2132.120 ;
        RECT 4.000 2107.680 2696.000 2130.760 ;
        RECT 4.400 2106.320 2696.000 2107.680 ;
        RECT 4.400 2106.280 2695.600 2106.320 ;
        RECT 4.000 2104.920 2695.600 2106.280 ;
        RECT 4.000 2083.200 2696.000 2104.920 ;
        RECT 4.400 2081.840 2696.000 2083.200 ;
        RECT 4.400 2081.800 2695.600 2081.840 ;
        RECT 4.000 2080.440 2695.600 2081.800 ;
        RECT 4.000 2057.360 2696.000 2080.440 ;
        RECT 4.400 2056.000 2696.000 2057.360 ;
        RECT 4.400 2055.960 2695.600 2056.000 ;
        RECT 4.000 2054.600 2695.600 2055.960 ;
        RECT 4.000 2032.880 2696.000 2054.600 ;
        RECT 4.400 2031.520 2696.000 2032.880 ;
        RECT 4.400 2031.480 2695.600 2031.520 ;
        RECT 4.000 2030.120 2695.600 2031.480 ;
        RECT 4.000 2008.400 2696.000 2030.120 ;
        RECT 4.400 2007.040 2696.000 2008.400 ;
        RECT 4.400 2007.000 2695.600 2007.040 ;
        RECT 4.000 2005.640 2695.600 2007.000 ;
        RECT 4.000 1982.560 2696.000 2005.640 ;
        RECT 4.400 1981.200 2696.000 1982.560 ;
        RECT 4.400 1981.160 2695.600 1981.200 ;
        RECT 4.000 1979.800 2695.600 1981.160 ;
        RECT 4.000 1958.080 2696.000 1979.800 ;
        RECT 4.400 1956.720 2696.000 1958.080 ;
        RECT 4.400 1956.680 2695.600 1956.720 ;
        RECT 4.000 1955.320 2695.600 1956.680 ;
        RECT 4.000 1932.240 2696.000 1955.320 ;
        RECT 4.400 1930.880 2696.000 1932.240 ;
        RECT 4.400 1930.840 2695.600 1930.880 ;
        RECT 4.000 1929.480 2695.600 1930.840 ;
        RECT 4.000 1907.760 2696.000 1929.480 ;
        RECT 4.400 1906.400 2696.000 1907.760 ;
        RECT 4.400 1906.360 2695.600 1906.400 ;
        RECT 4.000 1905.000 2695.600 1906.360 ;
        RECT 4.000 1883.280 2696.000 1905.000 ;
        RECT 4.400 1881.880 2696.000 1883.280 ;
        RECT 4.000 1880.560 2696.000 1881.880 ;
        RECT 4.000 1879.160 2695.600 1880.560 ;
        RECT 4.000 1857.440 2696.000 1879.160 ;
        RECT 4.400 1856.080 2696.000 1857.440 ;
        RECT 4.400 1856.040 2695.600 1856.080 ;
        RECT 4.000 1854.680 2695.600 1856.040 ;
        RECT 4.000 1832.960 2696.000 1854.680 ;
        RECT 4.400 1831.600 2696.000 1832.960 ;
        RECT 4.400 1831.560 2695.600 1831.600 ;
        RECT 4.000 1830.200 2695.600 1831.560 ;
        RECT 4.000 1807.120 2696.000 1830.200 ;
        RECT 4.400 1805.760 2696.000 1807.120 ;
        RECT 4.400 1805.720 2695.600 1805.760 ;
        RECT 4.000 1804.360 2695.600 1805.720 ;
        RECT 4.000 1782.640 2696.000 1804.360 ;
        RECT 4.400 1781.280 2696.000 1782.640 ;
        RECT 4.400 1781.240 2695.600 1781.280 ;
        RECT 4.000 1779.880 2695.600 1781.240 ;
        RECT 4.000 1758.160 2696.000 1779.880 ;
        RECT 4.400 1756.760 2696.000 1758.160 ;
        RECT 4.000 1755.440 2696.000 1756.760 ;
        RECT 4.000 1754.040 2695.600 1755.440 ;
        RECT 4.000 1732.320 2696.000 1754.040 ;
        RECT 4.400 1730.960 2696.000 1732.320 ;
        RECT 4.400 1730.920 2695.600 1730.960 ;
        RECT 4.000 1729.560 2695.600 1730.920 ;
        RECT 4.000 1707.840 2696.000 1729.560 ;
        RECT 4.400 1706.480 2696.000 1707.840 ;
        RECT 4.400 1706.440 2695.600 1706.480 ;
        RECT 4.000 1705.080 2695.600 1706.440 ;
        RECT 4.000 1682.000 2696.000 1705.080 ;
        RECT 4.400 1680.640 2696.000 1682.000 ;
        RECT 4.400 1680.600 2695.600 1680.640 ;
        RECT 4.000 1679.240 2695.600 1680.600 ;
        RECT 4.000 1657.520 2696.000 1679.240 ;
        RECT 4.400 1656.160 2696.000 1657.520 ;
        RECT 4.400 1656.120 2695.600 1656.160 ;
        RECT 4.000 1654.760 2695.600 1656.120 ;
        RECT 4.000 1631.680 2696.000 1654.760 ;
        RECT 4.400 1630.320 2696.000 1631.680 ;
        RECT 4.400 1630.280 2695.600 1630.320 ;
        RECT 4.000 1628.920 2695.600 1630.280 ;
        RECT 4.000 1607.200 2696.000 1628.920 ;
        RECT 4.400 1605.840 2696.000 1607.200 ;
        RECT 4.400 1605.800 2695.600 1605.840 ;
        RECT 4.000 1604.440 2695.600 1605.800 ;
        RECT 4.000 1582.720 2696.000 1604.440 ;
        RECT 4.400 1581.320 2696.000 1582.720 ;
        RECT 4.000 1580.000 2696.000 1581.320 ;
        RECT 4.000 1578.600 2695.600 1580.000 ;
        RECT 4.000 1556.880 2696.000 1578.600 ;
        RECT 4.400 1555.520 2696.000 1556.880 ;
        RECT 4.400 1555.480 2695.600 1555.520 ;
        RECT 4.000 1554.120 2695.600 1555.480 ;
        RECT 4.000 1532.400 2696.000 1554.120 ;
        RECT 4.400 1531.040 2696.000 1532.400 ;
        RECT 4.400 1531.000 2695.600 1531.040 ;
        RECT 4.000 1529.640 2695.600 1531.000 ;
        RECT 4.000 1506.560 2696.000 1529.640 ;
        RECT 4.400 1505.200 2696.000 1506.560 ;
        RECT 4.400 1505.160 2695.600 1505.200 ;
        RECT 4.000 1503.800 2695.600 1505.160 ;
        RECT 4.000 1482.080 2696.000 1503.800 ;
        RECT 4.400 1480.720 2696.000 1482.080 ;
        RECT 4.400 1480.680 2695.600 1480.720 ;
        RECT 4.000 1479.320 2695.600 1480.680 ;
        RECT 4.000 1457.600 2696.000 1479.320 ;
        RECT 4.400 1456.200 2696.000 1457.600 ;
        RECT 4.000 1454.880 2696.000 1456.200 ;
        RECT 4.000 1453.480 2695.600 1454.880 ;
        RECT 4.000 1431.760 2696.000 1453.480 ;
        RECT 4.400 1430.400 2696.000 1431.760 ;
        RECT 4.400 1430.360 2695.600 1430.400 ;
        RECT 4.000 1429.000 2695.600 1430.360 ;
        RECT 4.000 1407.280 2696.000 1429.000 ;
        RECT 4.400 1405.920 2696.000 1407.280 ;
        RECT 4.400 1405.880 2695.600 1405.920 ;
        RECT 4.000 1404.520 2695.600 1405.880 ;
        RECT 4.000 1381.440 2696.000 1404.520 ;
        RECT 4.400 1380.080 2696.000 1381.440 ;
        RECT 4.400 1380.040 2695.600 1380.080 ;
        RECT 4.000 1378.680 2695.600 1380.040 ;
        RECT 4.000 1356.960 2696.000 1378.680 ;
        RECT 4.400 1355.600 2696.000 1356.960 ;
        RECT 4.400 1355.560 2695.600 1355.600 ;
        RECT 4.000 1354.200 2695.600 1355.560 ;
        RECT 4.000 1331.120 2696.000 1354.200 ;
        RECT 4.400 1329.760 2696.000 1331.120 ;
        RECT 4.400 1329.720 2695.600 1329.760 ;
        RECT 4.000 1328.360 2695.600 1329.720 ;
        RECT 4.000 1306.640 2696.000 1328.360 ;
        RECT 4.400 1305.280 2696.000 1306.640 ;
        RECT 4.400 1305.240 2695.600 1305.280 ;
        RECT 4.000 1303.880 2695.600 1305.240 ;
        RECT 4.000 1282.160 2696.000 1303.880 ;
        RECT 4.400 1280.800 2696.000 1282.160 ;
        RECT 4.400 1280.760 2695.600 1280.800 ;
        RECT 4.000 1279.400 2695.600 1280.760 ;
        RECT 4.000 1256.320 2696.000 1279.400 ;
        RECT 4.400 1254.960 2696.000 1256.320 ;
        RECT 4.400 1254.920 2695.600 1254.960 ;
        RECT 4.000 1253.560 2695.600 1254.920 ;
        RECT 4.000 1231.840 2696.000 1253.560 ;
        RECT 4.400 1230.480 2696.000 1231.840 ;
        RECT 4.400 1230.440 2695.600 1230.480 ;
        RECT 4.000 1229.080 2695.600 1230.440 ;
        RECT 4.000 1206.000 2696.000 1229.080 ;
        RECT 4.400 1204.640 2696.000 1206.000 ;
        RECT 4.400 1204.600 2695.600 1204.640 ;
        RECT 4.000 1203.240 2695.600 1204.600 ;
        RECT 4.000 1181.520 2696.000 1203.240 ;
        RECT 4.400 1180.160 2696.000 1181.520 ;
        RECT 4.400 1180.120 2695.600 1180.160 ;
        RECT 4.000 1178.760 2695.600 1180.120 ;
        RECT 4.000 1157.040 2696.000 1178.760 ;
        RECT 4.400 1155.640 2696.000 1157.040 ;
        RECT 4.000 1154.320 2696.000 1155.640 ;
        RECT 4.000 1152.920 2695.600 1154.320 ;
        RECT 4.000 1131.200 2696.000 1152.920 ;
        RECT 4.400 1129.840 2696.000 1131.200 ;
        RECT 4.400 1129.800 2695.600 1129.840 ;
        RECT 4.000 1128.440 2695.600 1129.800 ;
        RECT 4.000 1106.720 2696.000 1128.440 ;
        RECT 4.400 1105.360 2696.000 1106.720 ;
        RECT 4.400 1105.320 2695.600 1105.360 ;
        RECT 4.000 1103.960 2695.600 1105.320 ;
        RECT 4.000 1080.880 2696.000 1103.960 ;
        RECT 4.400 1079.520 2696.000 1080.880 ;
        RECT 4.400 1079.480 2695.600 1079.520 ;
        RECT 4.000 1078.120 2695.600 1079.480 ;
        RECT 4.000 1056.400 2696.000 1078.120 ;
        RECT 4.400 1055.040 2696.000 1056.400 ;
        RECT 4.400 1055.000 2695.600 1055.040 ;
        RECT 4.000 1053.640 2695.600 1055.000 ;
        RECT 4.000 1030.560 2696.000 1053.640 ;
        RECT 4.400 1029.200 2696.000 1030.560 ;
        RECT 4.400 1029.160 2695.600 1029.200 ;
        RECT 4.000 1027.800 2695.600 1029.160 ;
        RECT 4.000 1006.080 2696.000 1027.800 ;
        RECT 4.400 1004.720 2696.000 1006.080 ;
        RECT 4.400 1004.680 2695.600 1004.720 ;
        RECT 4.000 1003.320 2695.600 1004.680 ;
        RECT 4.000 981.600 2696.000 1003.320 ;
        RECT 4.400 980.240 2696.000 981.600 ;
        RECT 4.400 980.200 2695.600 980.240 ;
        RECT 4.000 978.840 2695.600 980.200 ;
        RECT 4.000 955.760 2696.000 978.840 ;
        RECT 4.400 954.400 2696.000 955.760 ;
        RECT 4.400 954.360 2695.600 954.400 ;
        RECT 4.000 953.000 2695.600 954.360 ;
        RECT 4.000 931.280 2696.000 953.000 ;
        RECT 4.400 929.920 2696.000 931.280 ;
        RECT 4.400 929.880 2695.600 929.920 ;
        RECT 4.000 928.520 2695.600 929.880 ;
        RECT 4.000 905.440 2696.000 928.520 ;
        RECT 4.400 904.080 2696.000 905.440 ;
        RECT 4.400 904.040 2695.600 904.080 ;
        RECT 4.000 902.680 2695.600 904.040 ;
        RECT 4.000 880.960 2696.000 902.680 ;
        RECT 4.400 879.600 2696.000 880.960 ;
        RECT 4.400 879.560 2695.600 879.600 ;
        RECT 4.000 878.200 2695.600 879.560 ;
        RECT 4.000 856.480 2696.000 878.200 ;
        RECT 4.400 855.080 2696.000 856.480 ;
        RECT 4.000 853.760 2696.000 855.080 ;
        RECT 4.000 852.360 2695.600 853.760 ;
        RECT 4.000 830.640 2696.000 852.360 ;
        RECT 4.400 829.280 2696.000 830.640 ;
        RECT 4.400 829.240 2695.600 829.280 ;
        RECT 4.000 827.880 2695.600 829.240 ;
        RECT 4.000 806.160 2696.000 827.880 ;
        RECT 4.400 804.800 2696.000 806.160 ;
        RECT 4.400 804.760 2695.600 804.800 ;
        RECT 4.000 803.400 2695.600 804.760 ;
        RECT 4.000 780.320 2696.000 803.400 ;
        RECT 4.400 778.960 2696.000 780.320 ;
        RECT 4.400 778.920 2695.600 778.960 ;
        RECT 4.000 777.560 2695.600 778.920 ;
        RECT 4.000 755.840 2696.000 777.560 ;
        RECT 4.400 754.480 2696.000 755.840 ;
        RECT 4.400 754.440 2695.600 754.480 ;
        RECT 4.000 753.080 2695.600 754.440 ;
        RECT 4.000 731.360 2696.000 753.080 ;
        RECT 4.400 729.960 2696.000 731.360 ;
        RECT 4.000 728.640 2696.000 729.960 ;
        RECT 4.000 727.240 2695.600 728.640 ;
        RECT 4.000 705.520 2696.000 727.240 ;
        RECT 4.400 704.160 2696.000 705.520 ;
        RECT 4.400 704.120 2695.600 704.160 ;
        RECT 4.000 702.760 2695.600 704.120 ;
        RECT 4.000 681.040 2696.000 702.760 ;
        RECT 4.400 679.680 2696.000 681.040 ;
        RECT 4.400 679.640 2695.600 679.680 ;
        RECT 4.000 678.280 2695.600 679.640 ;
        RECT 4.000 655.200 2696.000 678.280 ;
        RECT 4.400 653.840 2696.000 655.200 ;
        RECT 4.400 653.800 2695.600 653.840 ;
        RECT 4.000 652.440 2695.600 653.800 ;
        RECT 4.000 630.720 2696.000 652.440 ;
        RECT 4.400 629.360 2696.000 630.720 ;
        RECT 4.400 629.320 2695.600 629.360 ;
        RECT 4.000 627.960 2695.600 629.320 ;
        RECT 4.000 604.880 2696.000 627.960 ;
        RECT 4.400 603.520 2696.000 604.880 ;
        RECT 4.400 603.480 2695.600 603.520 ;
        RECT 4.000 602.120 2695.600 603.480 ;
        RECT 4.000 580.400 2696.000 602.120 ;
        RECT 4.400 579.040 2696.000 580.400 ;
        RECT 4.400 579.000 2695.600 579.040 ;
        RECT 4.000 577.640 2695.600 579.000 ;
        RECT 4.000 555.920 2696.000 577.640 ;
        RECT 4.400 554.520 2696.000 555.920 ;
        RECT 4.000 553.200 2696.000 554.520 ;
        RECT 4.000 551.800 2695.600 553.200 ;
        RECT 4.000 530.080 2696.000 551.800 ;
        RECT 4.400 528.720 2696.000 530.080 ;
        RECT 4.400 528.680 2695.600 528.720 ;
        RECT 4.000 527.320 2695.600 528.680 ;
        RECT 4.000 505.600 2696.000 527.320 ;
        RECT 4.400 504.240 2696.000 505.600 ;
        RECT 4.400 504.200 2695.600 504.240 ;
        RECT 4.000 502.840 2695.600 504.200 ;
        RECT 4.000 479.760 2696.000 502.840 ;
        RECT 4.400 478.400 2696.000 479.760 ;
        RECT 4.400 478.360 2695.600 478.400 ;
        RECT 4.000 477.000 2695.600 478.360 ;
        RECT 4.000 455.280 2696.000 477.000 ;
        RECT 4.400 453.920 2696.000 455.280 ;
        RECT 4.400 453.880 2695.600 453.920 ;
        RECT 4.000 452.520 2695.600 453.880 ;
        RECT 4.000 430.800 2696.000 452.520 ;
        RECT 4.400 429.400 2696.000 430.800 ;
        RECT 4.000 428.080 2696.000 429.400 ;
        RECT 4.000 426.680 2695.600 428.080 ;
        RECT 4.000 404.960 2696.000 426.680 ;
        RECT 4.400 403.600 2696.000 404.960 ;
        RECT 4.400 403.560 2695.600 403.600 ;
        RECT 4.000 402.200 2695.600 403.560 ;
        RECT 4.000 380.480 2696.000 402.200 ;
        RECT 4.400 379.120 2696.000 380.480 ;
        RECT 4.400 379.080 2695.600 379.120 ;
        RECT 4.000 377.720 2695.600 379.080 ;
        RECT 4.000 354.640 2696.000 377.720 ;
        RECT 4.400 353.280 2696.000 354.640 ;
        RECT 4.400 353.240 2695.600 353.280 ;
        RECT 4.000 351.880 2695.600 353.240 ;
        RECT 4.000 330.160 2696.000 351.880 ;
        RECT 4.400 328.800 2696.000 330.160 ;
        RECT 4.400 328.760 2695.600 328.800 ;
        RECT 4.000 327.400 2695.600 328.760 ;
        RECT 4.000 304.320 2696.000 327.400 ;
        RECT 4.400 302.960 2696.000 304.320 ;
        RECT 4.400 302.920 2695.600 302.960 ;
        RECT 4.000 301.560 2695.600 302.920 ;
        RECT 4.000 279.840 2696.000 301.560 ;
        RECT 4.400 278.480 2696.000 279.840 ;
        RECT 4.400 278.440 2695.600 278.480 ;
        RECT 4.000 277.080 2695.600 278.440 ;
        RECT 4.000 255.360 2696.000 277.080 ;
        RECT 4.400 254.000 2696.000 255.360 ;
        RECT 4.400 253.960 2695.600 254.000 ;
        RECT 4.000 252.600 2695.600 253.960 ;
        RECT 4.000 229.520 2696.000 252.600 ;
        RECT 4.400 228.160 2696.000 229.520 ;
        RECT 4.400 228.120 2695.600 228.160 ;
        RECT 4.000 226.760 2695.600 228.120 ;
        RECT 4.000 205.040 2696.000 226.760 ;
        RECT 4.400 203.680 2696.000 205.040 ;
        RECT 4.400 203.640 2695.600 203.680 ;
        RECT 4.000 202.280 2695.600 203.640 ;
        RECT 4.000 179.200 2696.000 202.280 ;
        RECT 4.400 177.840 2696.000 179.200 ;
        RECT 4.400 177.800 2695.600 177.840 ;
        RECT 4.000 176.440 2695.600 177.800 ;
        RECT 4.000 154.720 2696.000 176.440 ;
        RECT 4.400 153.360 2696.000 154.720 ;
        RECT 4.400 153.320 2695.600 153.360 ;
        RECT 4.000 151.960 2695.600 153.320 ;
        RECT 4.000 130.240 2696.000 151.960 ;
        RECT 4.400 128.840 2696.000 130.240 ;
        RECT 4.000 127.520 2696.000 128.840 ;
        RECT 4.000 126.120 2695.600 127.520 ;
        RECT 4.000 104.400 2696.000 126.120 ;
        RECT 4.400 103.040 2696.000 104.400 ;
        RECT 4.400 103.000 2695.600 103.040 ;
        RECT 4.000 101.640 2695.600 103.000 ;
        RECT 4.000 79.920 2696.000 101.640 ;
        RECT 4.400 78.560 2696.000 79.920 ;
        RECT 4.400 78.520 2695.600 78.560 ;
        RECT 4.000 77.160 2695.600 78.520 ;
        RECT 4.000 54.080 2696.000 77.160 ;
        RECT 4.400 52.720 2696.000 54.080 ;
        RECT 4.400 52.680 2695.600 52.720 ;
        RECT 4.000 51.320 2695.600 52.680 ;
        RECT 4.000 29.600 2696.000 51.320 ;
        RECT 4.400 28.240 2696.000 29.600 ;
        RECT 4.400 28.200 2695.600 28.240 ;
        RECT 4.000 27.375 2695.600 28.200 ;
      LAYER met4 ;
        RECT 164.055 493.175 1787.265 3540.585 ;
      LAYER met5 ;
        RECT 1360.520 3026.490 1599.260 3181.270 ;
  END
END user_project_wrapper
END LIBRARY

